# Generated by FakeRAM 2.0
VERSION 5.7 ;
BUSBITCHARS "[]" ;
PROPERTYDEFINITIONS
  MACRO width INTEGER ;
  MACRO depth INTEGER ;
  MACRO banks INTEGER ;
END PROPERTYDEFINITIONS
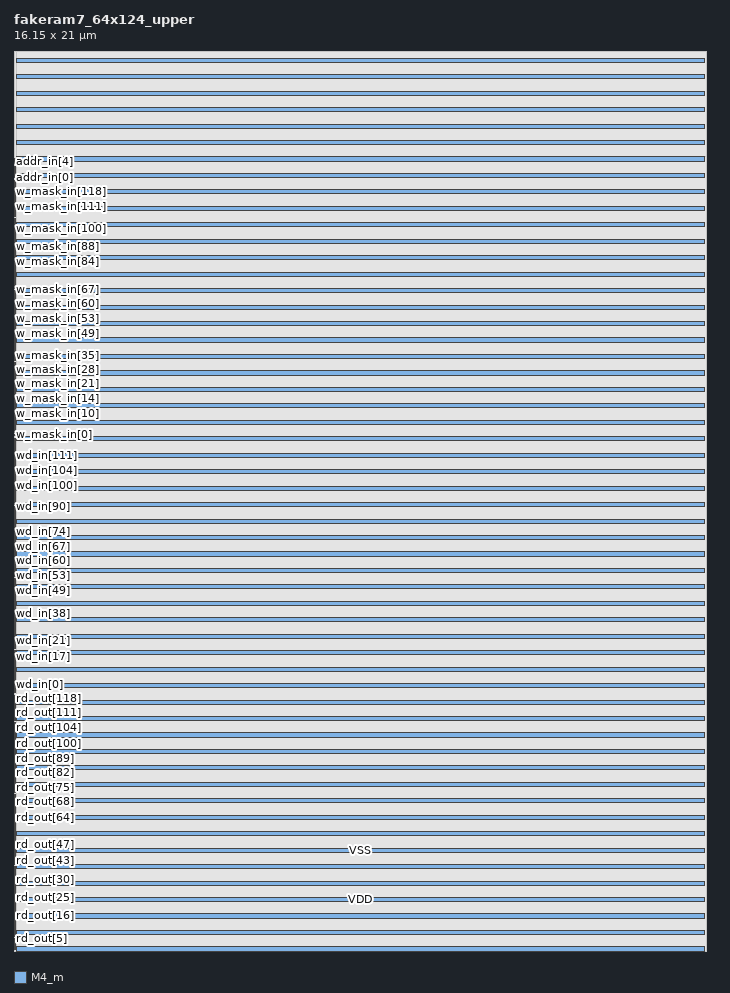
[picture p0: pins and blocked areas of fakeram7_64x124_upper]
MACRO fakeram7_64x124_upper
  PROPERTY width 124 ;
  PROPERTY depth 64 ;
  PROPERTY banks 2 ;
  FOREIGN fakeram7_64x124_upper 0 0 ;
  SYMMETRY X R90 ;
  SIZE 16.150 BY 21.000 ;
  CLASS BLOCK ;
  PIN rd_out[0]
    DIRECTION OUTPUT ;
    USE SIGNAL ;
    SHAPE ABUTMENT ;
    PORT
      LAYER M4_m ;
      RECT 0.000 0.039 0.024 0.063 ;
    END
  END rd_out[0]
  PIN rd_out[1]
    DIRECTION OUTPUT ;
    USE SIGNAL ;
    SHAPE ABUTMENT ;
    PORT
      LAYER M4_m ;
      RECT 0.000 0.087 0.024 0.111 ;
    END
  END rd_out[1]
  PIN rd_out[2]
    DIRECTION OUTPUT ;
    USE SIGNAL ;
    SHAPE ABUTMENT ;
    PORT
      LAYER M4_m ;
      RECT 0.000 0.135 0.024 0.159 ;
    END
  END rd_out[2]
  PIN rd_out[3]
    DIRECTION OUTPUT ;
    USE SIGNAL ;
    SHAPE ABUTMENT ;
    PORT
      LAYER M4_m ;
      RECT 0.000 0.183 0.024 0.207 ;
    END
  END rd_out[3]
  PIN rd_out[4]
    DIRECTION OUTPUT ;
    USE SIGNAL ;
    SHAPE ABUTMENT ;
    PORT
      LAYER M4_m ;
      RECT 0.000 0.231 0.024 0.255 ;
    END
  END rd_out[4]
  PIN rd_out[5]
    DIRECTION OUTPUT ;
    USE SIGNAL ;
    SHAPE ABUTMENT ;
    PORT
      LAYER M4_m ;
      RECT 0.000 0.279 0.024 0.303 ;
    END
  END rd_out[5]
  PIN rd_out[6]
    DIRECTION OUTPUT ;
    USE SIGNAL ;
    SHAPE ABUTMENT ;
    PORT
      LAYER M4_m ;
      RECT 0.000 0.327 0.024 0.351 ;
    END
  END rd_out[6]
  PIN rd_out[7]
    DIRECTION OUTPUT ;
    USE SIGNAL ;
    SHAPE ABUTMENT ;
    PORT
      LAYER M4_m ;
      RECT 0.000 0.375 0.024 0.399 ;
    END
  END rd_out[7]
  PIN rd_out[8]
    DIRECTION OUTPUT ;
    USE SIGNAL ;
    SHAPE ABUTMENT ;
    PORT
      LAYER M4_m ;
      RECT 0.000 0.423 0.024 0.447 ;
    END
  END rd_out[8]
  PIN rd_out[9]
    DIRECTION OUTPUT ;
    USE SIGNAL ;
    SHAPE ABUTMENT ;
    PORT
      LAYER M4_m ;
      RECT 0.000 0.471 0.024 0.495 ;
    END
  END rd_out[9]
  PIN rd_out[10]
    DIRECTION OUTPUT ;
    USE SIGNAL ;
    SHAPE ABUTMENT ;
    PORT
      LAYER M4_m ;
      RECT 0.000 0.519 0.024 0.543 ;
    END
  END rd_out[10]
  PIN rd_out[11]
    DIRECTION OUTPUT ;
    USE SIGNAL ;
    SHAPE ABUTMENT ;
    PORT
      LAYER M4_m ;
      RECT 0.000 0.567 0.024 0.591 ;
    END
  END rd_out[11]
  PIN rd_out[12]
    DIRECTION OUTPUT ;
    USE SIGNAL ;
    SHAPE ABUTMENT ;
    PORT
      LAYER M4_m ;
      RECT 0.000 0.615 0.024 0.639 ;
    END
  END rd_out[12]
  PIN rd_out[13]
    DIRECTION OUTPUT ;
    USE SIGNAL ;
    SHAPE ABUTMENT ;
    PORT
      LAYER M4_m ;
      RECT 0.000 0.663 0.024 0.687 ;
    END
  END rd_out[13]
  PIN rd_out[14]
    DIRECTION OUTPUT ;
    USE SIGNAL ;
    SHAPE ABUTMENT ;
    PORT
      LAYER M4_m ;
      RECT 0.000 0.711 0.024 0.735 ;
    END
  END rd_out[14]
  PIN rd_out[15]
    DIRECTION OUTPUT ;
    USE SIGNAL ;
    SHAPE ABUTMENT ;
    PORT
      LAYER M4_m ;
      RECT 0.000 0.759 0.024 0.783 ;
    END
  END rd_out[15]
  PIN rd_out[16]
    DIRECTION OUTPUT ;
    USE SIGNAL ;
    SHAPE ABUTMENT ;
    PORT
      LAYER M4_m ;
      RECT 0.000 0.807 0.024 0.831 ;
    END
  END rd_out[16]
  PIN rd_out[17]
    DIRECTION OUTPUT ;
    USE SIGNAL ;
    SHAPE ABUTMENT ;
    PORT
      LAYER M4_m ;
      RECT 0.000 0.855 0.024 0.879 ;
    END
  END rd_out[17]
  PIN rd_out[18]
    DIRECTION OUTPUT ;
    USE SIGNAL ;
    SHAPE ABUTMENT ;
    PORT
      LAYER M4_m ;
      RECT 0.000 0.903 0.024 0.927 ;
    END
  END rd_out[18]
  PIN rd_out[19]
    DIRECTION OUTPUT ;
    USE SIGNAL ;
    SHAPE ABUTMENT ;
    PORT
      LAYER M4_m ;
      RECT 0.000 0.951 0.024 0.975 ;
    END
  END rd_out[19]
  PIN rd_out[20]
    DIRECTION OUTPUT ;
    USE SIGNAL ;
    SHAPE ABUTMENT ;
    PORT
      LAYER M4_m ;
      RECT 0.000 0.999 0.024 1.023 ;
    END
  END rd_out[20]
  PIN rd_out[21]
    DIRECTION OUTPUT ;
    USE SIGNAL ;
    SHAPE ABUTMENT ;
    PORT
      LAYER M4_m ;
      RECT 0.000 1.047 0.024 1.071 ;
    END
  END rd_out[21]
  PIN rd_out[22]
    DIRECTION OUTPUT ;
    USE SIGNAL ;
    SHAPE ABUTMENT ;
    PORT
      LAYER M4_m ;
      RECT 0.000 1.095 0.024 1.119 ;
    END
  END rd_out[22]
  PIN rd_out[23]
    DIRECTION OUTPUT ;
    USE SIGNAL ;
    SHAPE ABUTMENT ;
    PORT
      LAYER M4_m ;
      RECT 0.000 1.143 0.024 1.167 ;
    END
  END rd_out[23]
  PIN rd_out[24]
    DIRECTION OUTPUT ;
    USE SIGNAL ;
    SHAPE ABUTMENT ;
    PORT
      LAYER M4_m ;
      RECT 0.000 1.191 0.024 1.215 ;
    END
  END rd_out[24]
  PIN rd_out[25]
    DIRECTION OUTPUT ;
    USE SIGNAL ;
    SHAPE ABUTMENT ;
    PORT
      LAYER M4_m ;
      RECT 0.000 1.239 0.024 1.263 ;
    END
  END rd_out[25]
  PIN rd_out[26]
    DIRECTION OUTPUT ;
    USE SIGNAL ;
    SHAPE ABUTMENT ;
    PORT
      LAYER M4_m ;
      RECT 0.000 1.287 0.024 1.311 ;
    END
  END rd_out[26]
  PIN rd_out[27]
    DIRECTION OUTPUT ;
    USE SIGNAL ;
    SHAPE ABUTMENT ;
    PORT
      LAYER M4_m ;
      RECT 0.000 1.335 0.024 1.359 ;
    END
  END rd_out[27]
  PIN rd_out[28]
    DIRECTION OUTPUT ;
    USE SIGNAL ;
    SHAPE ABUTMENT ;
    PORT
      LAYER M4_m ;
      RECT 0.000 1.383 0.024 1.407 ;
    END
  END rd_out[28]
  PIN rd_out[29]
    DIRECTION OUTPUT ;
    USE SIGNAL ;
    SHAPE ABUTMENT ;
    PORT
      LAYER M4_m ;
      RECT 0.000 1.431 0.024 1.455 ;
    END
  END rd_out[29]
  PIN rd_out[30]
    DIRECTION OUTPUT ;
    USE SIGNAL ;
    SHAPE ABUTMENT ;
    PORT
      LAYER M4_m ;
      RECT 0.000 1.479 0.024 1.503 ;
    END
  END rd_out[30]
  PIN rd_out[31]
    DIRECTION OUTPUT ;
    USE SIGNAL ;
    SHAPE ABUTMENT ;
    PORT
      LAYER M4_m ;
      RECT 0.000 1.527 0.024 1.551 ;
    END
  END rd_out[31]
  PIN rd_out[32]
    DIRECTION OUTPUT ;
    USE SIGNAL ;
    SHAPE ABUTMENT ;
    PORT
      LAYER M4_m ;
      RECT 0.000 1.575 0.024 1.599 ;
    END
  END rd_out[32]
  PIN rd_out[33]
    DIRECTION OUTPUT ;
    USE SIGNAL ;
    SHAPE ABUTMENT ;
    PORT
      LAYER M4_m ;
      RECT 0.000 1.623 0.024 1.647 ;
    END
  END rd_out[33]
  PIN rd_out[34]
    DIRECTION OUTPUT ;
    USE SIGNAL ;
    SHAPE ABUTMENT ;
    PORT
      LAYER M4_m ;
      RECT 0.000 1.671 0.024 1.695 ;
    END
  END rd_out[34]
  PIN rd_out[35]
    DIRECTION OUTPUT ;
    USE SIGNAL ;
    SHAPE ABUTMENT ;
    PORT
      LAYER M4_m ;
      RECT 0.000 1.719 0.024 1.743 ;
    END
  END rd_out[35]
  PIN rd_out[36]
    DIRECTION OUTPUT ;
    USE SIGNAL ;
    SHAPE ABUTMENT ;
    PORT
      LAYER M4_m ;
      RECT 0.000 1.767 0.024 1.791 ;
    END
  END rd_out[36]
  PIN rd_out[37]
    DIRECTION OUTPUT ;
    USE SIGNAL ;
    SHAPE ABUTMENT ;
    PORT
      LAYER M4_m ;
      RECT 0.000 1.815 0.024 1.839 ;
    END
  END rd_out[37]
  PIN rd_out[38]
    DIRECTION OUTPUT ;
    USE SIGNAL ;
    SHAPE ABUTMENT ;
    PORT
      LAYER M4_m ;
      RECT 0.000 1.863 0.024 1.887 ;
    END
  END rd_out[38]
  PIN rd_out[39]
    DIRECTION OUTPUT ;
    USE SIGNAL ;
    SHAPE ABUTMENT ;
    PORT
      LAYER M4_m ;
      RECT 0.000 1.911 0.024 1.935 ;
    END
  END rd_out[39]
  PIN rd_out[40]
    DIRECTION OUTPUT ;
    USE SIGNAL ;
    SHAPE ABUTMENT ;
    PORT
      LAYER M4_m ;
      RECT 0.000 1.959 0.024 1.983 ;
    END
  END rd_out[40]
  PIN rd_out[41]
    DIRECTION OUTPUT ;
    USE SIGNAL ;
    SHAPE ABUTMENT ;
    PORT
      LAYER M4_m ;
      RECT 0.000 2.007 0.024 2.031 ;
    END
  END rd_out[41]
  PIN rd_out[42]
    DIRECTION OUTPUT ;
    USE SIGNAL ;
    SHAPE ABUTMENT ;
    PORT
      LAYER M4_m ;
      RECT 0.000 2.055 0.024 2.079 ;
    END
  END rd_out[42]
  PIN rd_out[43]
    DIRECTION OUTPUT ;
    USE SIGNAL ;
    SHAPE ABUTMENT ;
    PORT
      LAYER M4_m ;
      RECT 0.000 2.103 0.024 2.127 ;
    END
  END rd_out[43]
  PIN rd_out[44]
    DIRECTION OUTPUT ;
    USE SIGNAL ;
    SHAPE ABUTMENT ;
    PORT
      LAYER M4_m ;
      RECT 0.000 2.151 0.024 2.175 ;
    END
  END rd_out[44]
  PIN rd_out[45]
    DIRECTION OUTPUT ;
    USE SIGNAL ;
    SHAPE ABUTMENT ;
    PORT
      LAYER M4_m ;
      RECT 0.000 2.199 0.024 2.223 ;
    END
  END rd_out[45]
  PIN rd_out[46]
    DIRECTION OUTPUT ;
    USE SIGNAL ;
    SHAPE ABUTMENT ;
    PORT
      LAYER M4_m ;
      RECT 0.000 2.247 0.024 2.271 ;
    END
  END rd_out[46]
  PIN rd_out[47]
    DIRECTION OUTPUT ;
    USE SIGNAL ;
    SHAPE ABUTMENT ;
    PORT
      LAYER M4_m ;
      RECT 0.000 2.295 0.024 2.319 ;
    END
  END rd_out[47]
  PIN rd_out[48]
    DIRECTION OUTPUT ;
    USE SIGNAL ;
    SHAPE ABUTMENT ;
    PORT
      LAYER M4_m ;
      RECT 0.000 2.343 0.024 2.367 ;
    END
  END rd_out[48]
  PIN rd_out[49]
    DIRECTION OUTPUT ;
    USE SIGNAL ;
    SHAPE ABUTMENT ;
    PORT
      LAYER M4_m ;
      RECT 0.000 2.391 0.024 2.415 ;
    END
  END rd_out[49]
  PIN rd_out[50]
    DIRECTION OUTPUT ;
    USE SIGNAL ;
    SHAPE ABUTMENT ;
    PORT
      LAYER M4_m ;
      RECT 0.000 2.439 0.024 2.463 ;
    END
  END rd_out[50]
  PIN rd_out[51]
    DIRECTION OUTPUT ;
    USE SIGNAL ;
    SHAPE ABUTMENT ;
    PORT
      LAYER M4_m ;
      RECT 0.000 2.487 0.024 2.511 ;
    END
  END rd_out[51]
  PIN rd_out[52]
    DIRECTION OUTPUT ;
    USE SIGNAL ;
    SHAPE ABUTMENT ;
    PORT
      LAYER M4_m ;
      RECT 0.000 2.535 0.024 2.559 ;
    END
  END rd_out[52]
  PIN rd_out[53]
    DIRECTION OUTPUT ;
    USE SIGNAL ;
    SHAPE ABUTMENT ;
    PORT
      LAYER M4_m ;
      RECT 0.000 2.583 0.024 2.607 ;
    END
  END rd_out[53]
  PIN rd_out[54]
    DIRECTION OUTPUT ;
    USE SIGNAL ;
    SHAPE ABUTMENT ;
    PORT
      LAYER M4_m ;
      RECT 0.000 2.631 0.024 2.655 ;
    END
  END rd_out[54]
  PIN rd_out[55]
    DIRECTION OUTPUT ;
    USE SIGNAL ;
    SHAPE ABUTMENT ;
    PORT
      LAYER M4_m ;
      RECT 0.000 2.679 0.024 2.703 ;
    END
  END rd_out[55]
  PIN rd_out[56]
    DIRECTION OUTPUT ;
    USE SIGNAL ;
    SHAPE ABUTMENT ;
    PORT
      LAYER M4_m ;
      RECT 0.000 2.727 0.024 2.751 ;
    END
  END rd_out[56]
  PIN rd_out[57]
    DIRECTION OUTPUT ;
    USE SIGNAL ;
    SHAPE ABUTMENT ;
    PORT
      LAYER M4_m ;
      RECT 0.000 2.775 0.024 2.799 ;
    END
  END rd_out[57]
  PIN rd_out[58]
    DIRECTION OUTPUT ;
    USE SIGNAL ;
    SHAPE ABUTMENT ;
    PORT
      LAYER M4_m ;
      RECT 0.000 2.823 0.024 2.847 ;
    END
  END rd_out[58]
  PIN rd_out[59]
    DIRECTION OUTPUT ;
    USE SIGNAL ;
    SHAPE ABUTMENT ;
    PORT
      LAYER M4_m ;
      RECT 0.000 2.871 0.024 2.895 ;
    END
  END rd_out[59]
  PIN rd_out[60]
    DIRECTION OUTPUT ;
    USE SIGNAL ;
    SHAPE ABUTMENT ;
    PORT
      LAYER M4_m ;
      RECT 0.000 2.919 0.024 2.943 ;
    END
  END rd_out[60]
  PIN rd_out[61]
    DIRECTION OUTPUT ;
    USE SIGNAL ;
    SHAPE ABUTMENT ;
    PORT
      LAYER M4_m ;
      RECT 0.000 2.967 0.024 2.991 ;
    END
  END rd_out[61]
  PIN rd_out[62]
    DIRECTION OUTPUT ;
    USE SIGNAL ;
    SHAPE ABUTMENT ;
    PORT
      LAYER M4_m ;
      RECT 0.000 3.015 0.024 3.039 ;
    END
  END rd_out[62]
  PIN rd_out[63]
    DIRECTION OUTPUT ;
    USE SIGNAL ;
    SHAPE ABUTMENT ;
    PORT
      LAYER M4_m ;
      RECT 0.000 3.063 0.024 3.087 ;
    END
  END rd_out[63]
  PIN rd_out[64]
    DIRECTION OUTPUT ;
    USE SIGNAL ;
    SHAPE ABUTMENT ;
    PORT
      LAYER M4_m ;
      RECT 0.000 3.111 0.024 3.135 ;
    END
  END rd_out[64]
  PIN rd_out[65]
    DIRECTION OUTPUT ;
    USE SIGNAL ;
    SHAPE ABUTMENT ;
    PORT
      LAYER M4_m ;
      RECT 0.000 3.159 0.024 3.183 ;
    END
  END rd_out[65]
  PIN rd_out[66]
    DIRECTION OUTPUT ;
    USE SIGNAL ;
    SHAPE ABUTMENT ;
    PORT
      LAYER M4_m ;
      RECT 0.000 3.207 0.024 3.231 ;
    END
  END rd_out[66]
  PIN rd_out[67]
    DIRECTION OUTPUT ;
    USE SIGNAL ;
    SHAPE ABUTMENT ;
    PORT
      LAYER M4_m ;
      RECT 0.000 3.255 0.024 3.279 ;
    END
  END rd_out[67]
  PIN rd_out[68]
    DIRECTION OUTPUT ;
    USE SIGNAL ;
    SHAPE ABUTMENT ;
    PORT
      LAYER M4_m ;
      RECT 0.000 3.303 0.024 3.327 ;
    END
  END rd_out[68]
  PIN rd_out[69]
    DIRECTION OUTPUT ;
    USE SIGNAL ;
    SHAPE ABUTMENT ;
    PORT
      LAYER M4_m ;
      RECT 0.000 3.351 0.024 3.375 ;
    END
  END rd_out[69]
  PIN rd_out[70]
    DIRECTION OUTPUT ;
    USE SIGNAL ;
    SHAPE ABUTMENT ;
    PORT
      LAYER M4_m ;
      RECT 0.000 3.399 0.024 3.423 ;
    END
  END rd_out[70]
  PIN rd_out[71]
    DIRECTION OUTPUT ;
    USE SIGNAL ;
    SHAPE ABUTMENT ;
    PORT
      LAYER M4_m ;
      RECT 0.000 3.447 0.024 3.471 ;
    END
  END rd_out[71]
  PIN rd_out[72]
    DIRECTION OUTPUT ;
    USE SIGNAL ;
    SHAPE ABUTMENT ;
    PORT
      LAYER M4_m ;
      RECT 0.000 3.495 0.024 3.519 ;
    END
  END rd_out[72]
  PIN rd_out[73]
    DIRECTION OUTPUT ;
    USE SIGNAL ;
    SHAPE ABUTMENT ;
    PORT
      LAYER M4_m ;
      RECT 0.000 3.543 0.024 3.567 ;
    END
  END rd_out[73]
  PIN rd_out[74]
    DIRECTION OUTPUT ;
    USE SIGNAL ;
    SHAPE ABUTMENT ;
    PORT
      LAYER M4_m ;
      RECT 0.000 3.591 0.024 3.615 ;
    END
  END rd_out[74]
  PIN rd_out[75]
    DIRECTION OUTPUT ;
    USE SIGNAL ;
    SHAPE ABUTMENT ;
    PORT
      LAYER M4_m ;
      RECT 0.000 3.639 0.024 3.663 ;
    END
  END rd_out[75]
  PIN rd_out[76]
    DIRECTION OUTPUT ;
    USE SIGNAL ;
    SHAPE ABUTMENT ;
    PORT
      LAYER M4_m ;
      RECT 0.000 3.687 0.024 3.711 ;
    END
  END rd_out[76]
  PIN rd_out[77]
    DIRECTION OUTPUT ;
    USE SIGNAL ;
    SHAPE ABUTMENT ;
    PORT
      LAYER M4_m ;
      RECT 0.000 3.735 0.024 3.759 ;
    END
  END rd_out[77]
  PIN rd_out[78]
    DIRECTION OUTPUT ;
    USE SIGNAL ;
    SHAPE ABUTMENT ;
    PORT
      LAYER M4_m ;
      RECT 0.000 3.783 0.024 3.807 ;
    END
  END rd_out[78]
  PIN rd_out[79]
    DIRECTION OUTPUT ;
    USE SIGNAL ;
    SHAPE ABUTMENT ;
    PORT
      LAYER M4_m ;
      RECT 0.000 3.831 0.024 3.855 ;
    END
  END rd_out[79]
  PIN rd_out[80]
    DIRECTION OUTPUT ;
    USE SIGNAL ;
    SHAPE ABUTMENT ;
    PORT
      LAYER M4_m ;
      RECT 0.000 3.879 0.024 3.903 ;
    END
  END rd_out[80]
  PIN rd_out[81]
    DIRECTION OUTPUT ;
    USE SIGNAL ;
    SHAPE ABUTMENT ;
    PORT
      LAYER M4_m ;
      RECT 0.000 3.927 0.024 3.951 ;
    END
  END rd_out[81]
  PIN rd_out[82]
    DIRECTION OUTPUT ;
    USE SIGNAL ;
    SHAPE ABUTMENT ;
    PORT
      LAYER M4_m ;
      RECT 0.000 3.975 0.024 3.999 ;
    END
  END rd_out[82]
  PIN rd_out[83]
    DIRECTION OUTPUT ;
    USE SIGNAL ;
    SHAPE ABUTMENT ;
    PORT
      LAYER M4_m ;
      RECT 0.000 4.023 0.024 4.047 ;
    END
  END rd_out[83]
  PIN rd_out[84]
    DIRECTION OUTPUT ;
    USE SIGNAL ;
    SHAPE ABUTMENT ;
    PORT
      LAYER M4_m ;
      RECT 0.000 4.071 0.024 4.095 ;
    END
  END rd_out[84]
  PIN rd_out[85]
    DIRECTION OUTPUT ;
    USE SIGNAL ;
    SHAPE ABUTMENT ;
    PORT
      LAYER M4_m ;
      RECT 0.000 4.119 0.024 4.143 ;
    END
  END rd_out[85]
  PIN rd_out[86]
    DIRECTION OUTPUT ;
    USE SIGNAL ;
    SHAPE ABUTMENT ;
    PORT
      LAYER M4_m ;
      RECT 0.000 4.167 0.024 4.191 ;
    END
  END rd_out[86]
  PIN rd_out[87]
    DIRECTION OUTPUT ;
    USE SIGNAL ;
    SHAPE ABUTMENT ;
    PORT
      LAYER M4_m ;
      RECT 0.000 4.215 0.024 4.239 ;
    END
  END rd_out[87]
  PIN rd_out[88]
    DIRECTION OUTPUT ;
    USE SIGNAL ;
    SHAPE ABUTMENT ;
    PORT
      LAYER M4_m ;
      RECT 0.000 4.263 0.024 4.287 ;
    END
  END rd_out[88]
  PIN rd_out[89]
    DIRECTION OUTPUT ;
    USE SIGNAL ;
    SHAPE ABUTMENT ;
    PORT
      LAYER M4_m ;
      RECT 0.000 4.311 0.024 4.335 ;
    END
  END rd_out[89]
  PIN rd_out[90]
    DIRECTION OUTPUT ;
    USE SIGNAL ;
    SHAPE ABUTMENT ;
    PORT
      LAYER M4_m ;
      RECT 0.000 4.359 0.024 4.383 ;
    END
  END rd_out[90]
  PIN rd_out[91]
    DIRECTION OUTPUT ;
    USE SIGNAL ;
    SHAPE ABUTMENT ;
    PORT
      LAYER M4_m ;
      RECT 0.000 4.407 0.024 4.431 ;
    END
  END rd_out[91]
  PIN rd_out[92]
    DIRECTION OUTPUT ;
    USE SIGNAL ;
    SHAPE ABUTMENT ;
    PORT
      LAYER M4_m ;
      RECT 0.000 4.455 0.024 4.479 ;
    END
  END rd_out[92]
  PIN rd_out[93]
    DIRECTION OUTPUT ;
    USE SIGNAL ;
    SHAPE ABUTMENT ;
    PORT
      LAYER M4_m ;
      RECT 0.000 4.503 0.024 4.527 ;
    END
  END rd_out[93]
  PIN rd_out[94]
    DIRECTION OUTPUT ;
    USE SIGNAL ;
    SHAPE ABUTMENT ;
    PORT
      LAYER M4_m ;
      RECT 0.000 4.551 0.024 4.575 ;
    END
  END rd_out[94]
  PIN rd_out[95]
    DIRECTION OUTPUT ;
    USE SIGNAL ;
    SHAPE ABUTMENT ;
    PORT
      LAYER M4_m ;
      RECT 0.000 4.599 0.024 4.623 ;
    END
  END rd_out[95]
  PIN rd_out[96]
    DIRECTION OUTPUT ;
    USE SIGNAL ;
    SHAPE ABUTMENT ;
    PORT
      LAYER M4_m ;
      RECT 0.000 4.647 0.024 4.671 ;
    END
  END rd_out[96]
  PIN rd_out[97]
    DIRECTION OUTPUT ;
    USE SIGNAL ;
    SHAPE ABUTMENT ;
    PORT
      LAYER M4_m ;
      RECT 0.000 4.695 0.024 4.719 ;
    END
  END rd_out[97]
  PIN rd_out[98]
    DIRECTION OUTPUT ;
    USE SIGNAL ;
    SHAPE ABUTMENT ;
    PORT
      LAYER M4_m ;
      RECT 0.000 4.743 0.024 4.767 ;
    END
  END rd_out[98]
  PIN rd_out[99]
    DIRECTION OUTPUT ;
    USE SIGNAL ;
    SHAPE ABUTMENT ;
    PORT
      LAYER M4_m ;
      RECT 0.000 4.791 0.024 4.815 ;
    END
  END rd_out[99]
  PIN rd_out[100]
    DIRECTION OUTPUT ;
    USE SIGNAL ;
    SHAPE ABUTMENT ;
    PORT
      LAYER M4_m ;
      RECT 0.000 4.839 0.024 4.863 ;
    END
  END rd_out[100]
  PIN rd_out[101]
    DIRECTION OUTPUT ;
    USE SIGNAL ;
    SHAPE ABUTMENT ;
    PORT
      LAYER M4_m ;
      RECT 0.000 4.887 0.024 4.911 ;
    END
  END rd_out[101]
  PIN rd_out[102]
    DIRECTION OUTPUT ;
    USE SIGNAL ;
    SHAPE ABUTMENT ;
    PORT
      LAYER M4_m ;
      RECT 0.000 4.935 0.024 4.959 ;
    END
  END rd_out[102]
  PIN rd_out[103]
    DIRECTION OUTPUT ;
    USE SIGNAL ;
    SHAPE ABUTMENT ;
    PORT
      LAYER M4_m ;
      RECT 0.000 4.983 0.024 5.007 ;
    END
  END rd_out[103]
  PIN rd_out[104]
    DIRECTION OUTPUT ;
    USE SIGNAL ;
    SHAPE ABUTMENT ;
    PORT
      LAYER M4_m ;
      RECT 0.000 5.031 0.024 5.055 ;
    END
  END rd_out[104]
  PIN rd_out[105]
    DIRECTION OUTPUT ;
    USE SIGNAL ;
    SHAPE ABUTMENT ;
    PORT
      LAYER M4_m ;
      RECT 0.000 5.079 0.024 5.103 ;
    END
  END rd_out[105]
  PIN rd_out[106]
    DIRECTION OUTPUT ;
    USE SIGNAL ;
    SHAPE ABUTMENT ;
    PORT
      LAYER M4_m ;
      RECT 0.000 5.127 0.024 5.151 ;
    END
  END rd_out[106]
  PIN rd_out[107]
    DIRECTION OUTPUT ;
    USE SIGNAL ;
    SHAPE ABUTMENT ;
    PORT
      LAYER M4_m ;
      RECT 0.000 5.175 0.024 5.199 ;
    END
  END rd_out[107]
  PIN rd_out[108]
    DIRECTION OUTPUT ;
    USE SIGNAL ;
    SHAPE ABUTMENT ;
    PORT
      LAYER M4_m ;
      RECT 0.000 5.223 0.024 5.247 ;
    END
  END rd_out[108]
  PIN rd_out[109]
    DIRECTION OUTPUT ;
    USE SIGNAL ;
    SHAPE ABUTMENT ;
    PORT
      LAYER M4_m ;
      RECT 0.000 5.271 0.024 5.295 ;
    END
  END rd_out[109]
  PIN rd_out[110]
    DIRECTION OUTPUT ;
    USE SIGNAL ;
    SHAPE ABUTMENT ;
    PORT
      LAYER M4_m ;
      RECT 0.000 5.319 0.024 5.343 ;
    END
  END rd_out[110]
  PIN rd_out[111]
    DIRECTION OUTPUT ;
    USE SIGNAL ;
    SHAPE ABUTMENT ;
    PORT
      LAYER M4_m ;
      RECT 0.000 5.367 0.024 5.391 ;
    END
  END rd_out[111]
  PIN rd_out[112]
    DIRECTION OUTPUT ;
    USE SIGNAL ;
    SHAPE ABUTMENT ;
    PORT
      LAYER M4_m ;
      RECT 0.000 5.415 0.024 5.439 ;
    END
  END rd_out[112]
  PIN rd_out[113]
    DIRECTION OUTPUT ;
    USE SIGNAL ;
    SHAPE ABUTMENT ;
    PORT
      LAYER M4_m ;
      RECT 0.000 5.463 0.024 5.487 ;
    END
  END rd_out[113]
  PIN rd_out[114]
    DIRECTION OUTPUT ;
    USE SIGNAL ;
    SHAPE ABUTMENT ;
    PORT
      LAYER M4_m ;
      RECT 0.000 5.511 0.024 5.535 ;
    END
  END rd_out[114]
  PIN rd_out[115]
    DIRECTION OUTPUT ;
    USE SIGNAL ;
    SHAPE ABUTMENT ;
    PORT
      LAYER M4_m ;
      RECT 0.000 5.559 0.024 5.583 ;
    END
  END rd_out[115]
  PIN rd_out[116]
    DIRECTION OUTPUT ;
    USE SIGNAL ;
    SHAPE ABUTMENT ;
    PORT
      LAYER M4_m ;
      RECT 0.000 5.607 0.024 5.631 ;
    END
  END rd_out[116]
  PIN rd_out[117]
    DIRECTION OUTPUT ;
    USE SIGNAL ;
    SHAPE ABUTMENT ;
    PORT
      LAYER M4_m ;
      RECT 0.000 5.655 0.024 5.679 ;
    END
  END rd_out[117]
  PIN rd_out[118]
    DIRECTION OUTPUT ;
    USE SIGNAL ;
    SHAPE ABUTMENT ;
    PORT
      LAYER M4_m ;
      RECT 0.000 5.703 0.024 5.727 ;
    END
  END rd_out[118]
  PIN rd_out[119]
    DIRECTION OUTPUT ;
    USE SIGNAL ;
    SHAPE ABUTMENT ;
    PORT
      LAYER M4_m ;
      RECT 0.000 5.751 0.024 5.775 ;
    END
  END rd_out[119]
  PIN rd_out[120]
    DIRECTION OUTPUT ;
    USE SIGNAL ;
    SHAPE ABUTMENT ;
    PORT
      LAYER M4_m ;
      RECT 0.000 5.799 0.024 5.823 ;
    END
  END rd_out[120]
  PIN rd_out[121]
    DIRECTION OUTPUT ;
    USE SIGNAL ;
    SHAPE ABUTMENT ;
    PORT
      LAYER M4_m ;
      RECT 0.000 5.847 0.024 5.871 ;
    END
  END rd_out[121]
  PIN rd_out[122]
    DIRECTION OUTPUT ;
    USE SIGNAL ;
    SHAPE ABUTMENT ;
    PORT
      LAYER M4_m ;
      RECT 0.000 5.895 0.024 5.919 ;
    END
  END rd_out[122]
  PIN rd_out[123]
    DIRECTION OUTPUT ;
    USE SIGNAL ;
    SHAPE ABUTMENT ;
    PORT
      LAYER M4_m ;
      RECT 0.000 5.943 0.024 5.967 ;
    END
  END rd_out[123]
  PIN wd_in[0]
    DIRECTION INPUT ;
    USE SIGNAL ;
    SHAPE ABUTMENT ;
    PORT
      LAYER M4_m ;
      RECT 0.000 6.039 0.024 6.063 ;
    END
  END wd_in[0]
  PIN wd_in[1]
    DIRECTION INPUT ;
    USE SIGNAL ;
    SHAPE ABUTMENT ;
    PORT
      LAYER M4_m ;
      RECT 0.000 6.087 0.024 6.111 ;
    END
  END wd_in[1]
  PIN wd_in[2]
    DIRECTION INPUT ;
    USE SIGNAL ;
    SHAPE ABUTMENT ;
    PORT
      LAYER M4_m ;
      RECT 0.000 6.135 0.024 6.159 ;
    END
  END wd_in[2]
  PIN wd_in[3]
    DIRECTION INPUT ;
    USE SIGNAL ;
    SHAPE ABUTMENT ;
    PORT
      LAYER M4_m ;
      RECT 0.000 6.183 0.024 6.207 ;
    END
  END wd_in[3]
  PIN wd_in[4]
    DIRECTION INPUT ;
    USE SIGNAL ;
    SHAPE ABUTMENT ;
    PORT
      LAYER M4_m ;
      RECT 0.000 6.231 0.024 6.255 ;
    END
  END wd_in[4]
  PIN wd_in[5]
    DIRECTION INPUT ;
    USE SIGNAL ;
    SHAPE ABUTMENT ;
    PORT
      LAYER M4_m ;
      RECT 0.000 6.279 0.024 6.303 ;
    END
  END wd_in[5]
  PIN wd_in[6]
    DIRECTION INPUT ;
    USE SIGNAL ;
    SHAPE ABUTMENT ;
    PORT
      LAYER M4_m ;
      RECT 0.000 6.327 0.024 6.351 ;
    END
  END wd_in[6]
  PIN wd_in[7]
    DIRECTION INPUT ;
    USE SIGNAL ;
    SHAPE ABUTMENT ;
    PORT
      LAYER M4_m ;
      RECT 0.000 6.375 0.024 6.399 ;
    END
  END wd_in[7]
  PIN wd_in[8]
    DIRECTION INPUT ;
    USE SIGNAL ;
    SHAPE ABUTMENT ;
    PORT
      LAYER M4_m ;
      RECT 0.000 6.423 0.024 6.447 ;
    END
  END wd_in[8]
  PIN wd_in[9]
    DIRECTION INPUT ;
    USE SIGNAL ;
    SHAPE ABUTMENT ;
    PORT
      LAYER M4_m ;
      RECT 0.000 6.471 0.024 6.495 ;
    END
  END wd_in[9]
  PIN wd_in[10]
    DIRECTION INPUT ;
    USE SIGNAL ;
    SHAPE ABUTMENT ;
    PORT
      LAYER M4_m ;
      RECT 0.000 6.519 0.024 6.543 ;
    END
  END wd_in[10]
  PIN wd_in[11]
    DIRECTION INPUT ;
    USE SIGNAL ;
    SHAPE ABUTMENT ;
    PORT
      LAYER M4_m ;
      RECT 0.000 6.567 0.024 6.591 ;
    END
  END wd_in[11]
  PIN wd_in[12]
    DIRECTION INPUT ;
    USE SIGNAL ;
    SHAPE ABUTMENT ;
    PORT
      LAYER M4_m ;
      RECT 0.000 6.615 0.024 6.639 ;
    END
  END wd_in[12]
  PIN wd_in[13]
    DIRECTION INPUT ;
    USE SIGNAL ;
    SHAPE ABUTMENT ;
    PORT
      LAYER M4_m ;
      RECT 0.000 6.663 0.024 6.687 ;
    END
  END wd_in[13]
  PIN wd_in[14]
    DIRECTION INPUT ;
    USE SIGNAL ;
    SHAPE ABUTMENT ;
    PORT
      LAYER M4_m ;
      RECT 0.000 6.711 0.024 6.735 ;
    END
  END wd_in[14]
  PIN wd_in[15]
    DIRECTION INPUT ;
    USE SIGNAL ;
    SHAPE ABUTMENT ;
    PORT
      LAYER M4_m ;
      RECT 0.000 6.759 0.024 6.783 ;
    END
  END wd_in[15]
  PIN wd_in[16]
    DIRECTION INPUT ;
    USE SIGNAL ;
    SHAPE ABUTMENT ;
    PORT
      LAYER M4_m ;
      RECT 0.000 6.807 0.024 6.831 ;
    END
  END wd_in[16]
  PIN wd_in[17]
    DIRECTION INPUT ;
    USE SIGNAL ;
    SHAPE ABUTMENT ;
    PORT
      LAYER M4_m ;
      RECT 0.000 6.855 0.024 6.879 ;
    END
  END wd_in[17]
  PIN wd_in[18]
    DIRECTION INPUT ;
    USE SIGNAL ;
    SHAPE ABUTMENT ;
    PORT
      LAYER M4_m ;
      RECT 0.000 6.903 0.024 6.927 ;
    END
  END wd_in[18]
  PIN wd_in[19]
    DIRECTION INPUT ;
    USE SIGNAL ;
    SHAPE ABUTMENT ;
    PORT
      LAYER M4_m ;
      RECT 0.000 6.951 0.024 6.975 ;
    END
  END wd_in[19]
  PIN wd_in[20]
    DIRECTION INPUT ;
    USE SIGNAL ;
    SHAPE ABUTMENT ;
    PORT
      LAYER M4_m ;
      RECT 0.000 6.999 0.024 7.023 ;
    END
  END wd_in[20]
  PIN wd_in[21]
    DIRECTION INPUT ;
    USE SIGNAL ;
    SHAPE ABUTMENT ;
    PORT
      LAYER M4_m ;
      RECT 0.000 7.047 0.024 7.071 ;
    END
  END wd_in[21]
  PIN wd_in[22]
    DIRECTION INPUT ;
    USE SIGNAL ;
    SHAPE ABUTMENT ;
    PORT
      LAYER M4_m ;
      RECT 0.000 7.095 0.024 7.119 ;
    END
  END wd_in[22]
  PIN wd_in[23]
    DIRECTION INPUT ;
    USE SIGNAL ;
    SHAPE ABUTMENT ;
    PORT
      LAYER M4_m ;
      RECT 0.000 7.143 0.024 7.167 ;
    END
  END wd_in[23]
  PIN wd_in[24]
    DIRECTION INPUT ;
    USE SIGNAL ;
    SHAPE ABUTMENT ;
    PORT
      LAYER M4_m ;
      RECT 0.000 7.191 0.024 7.215 ;
    END
  END wd_in[24]
  PIN wd_in[25]
    DIRECTION INPUT ;
    USE SIGNAL ;
    SHAPE ABUTMENT ;
    PORT
      LAYER M4_m ;
      RECT 0.000 7.239 0.024 7.263 ;
    END
  END wd_in[25]
  PIN wd_in[26]
    DIRECTION INPUT ;
    USE SIGNAL ;
    SHAPE ABUTMENT ;
    PORT
      LAYER M4_m ;
      RECT 0.000 7.287 0.024 7.311 ;
    END
  END wd_in[26]
  PIN wd_in[27]
    DIRECTION INPUT ;
    USE SIGNAL ;
    SHAPE ABUTMENT ;
    PORT
      LAYER M4_m ;
      RECT 0.000 7.335 0.024 7.359 ;
    END
  END wd_in[27]
  PIN wd_in[28]
    DIRECTION INPUT ;
    USE SIGNAL ;
    SHAPE ABUTMENT ;
    PORT
      LAYER M4_m ;
      RECT 0.000 7.383 0.024 7.407 ;
    END
  END wd_in[28]
  PIN wd_in[29]
    DIRECTION INPUT ;
    USE SIGNAL ;
    SHAPE ABUTMENT ;
    PORT
      LAYER M4_m ;
      RECT 0.000 7.431 0.024 7.455 ;
    END
  END wd_in[29]
  PIN wd_in[30]
    DIRECTION INPUT ;
    USE SIGNAL ;
    SHAPE ABUTMENT ;
    PORT
      LAYER M4_m ;
      RECT 0.000 7.479 0.024 7.503 ;
    END
  END wd_in[30]
  PIN wd_in[31]
    DIRECTION INPUT ;
    USE SIGNAL ;
    SHAPE ABUTMENT ;
    PORT
      LAYER M4_m ;
      RECT 0.000 7.527 0.024 7.551 ;
    END
  END wd_in[31]
  PIN wd_in[32]
    DIRECTION INPUT ;
    USE SIGNAL ;
    SHAPE ABUTMENT ;
    PORT
      LAYER M4_m ;
      RECT 0.000 7.575 0.024 7.599 ;
    END
  END wd_in[32]
  PIN wd_in[33]
    DIRECTION INPUT ;
    USE SIGNAL ;
    SHAPE ABUTMENT ;
    PORT
      LAYER M4_m ;
      RECT 0.000 7.623 0.024 7.647 ;
    END
  END wd_in[33]
  PIN wd_in[34]
    DIRECTION INPUT ;
    USE SIGNAL ;
    SHAPE ABUTMENT ;
    PORT
      LAYER M4_m ;
      RECT 0.000 7.671 0.024 7.695 ;
    END
  END wd_in[34]
  PIN wd_in[35]
    DIRECTION INPUT ;
    USE SIGNAL ;
    SHAPE ABUTMENT ;
    PORT
      LAYER M4_m ;
      RECT 0.000 7.719 0.024 7.743 ;
    END
  END wd_in[35]
  PIN wd_in[36]
    DIRECTION INPUT ;
    USE SIGNAL ;
    SHAPE ABUTMENT ;
    PORT
      LAYER M4_m ;
      RECT 0.000 7.767 0.024 7.791 ;
    END
  END wd_in[36]
  PIN wd_in[37]
    DIRECTION INPUT ;
    USE SIGNAL ;
    SHAPE ABUTMENT ;
    PORT
      LAYER M4_m ;
      RECT 0.000 7.815 0.024 7.839 ;
    END
  END wd_in[37]
  PIN wd_in[38]
    DIRECTION INPUT ;
    USE SIGNAL ;
    SHAPE ABUTMENT ;
    PORT
      LAYER M4_m ;
      RECT 0.000 7.863 0.024 7.887 ;
    END
  END wd_in[38]
  PIN wd_in[39]
    DIRECTION INPUT ;
    USE SIGNAL ;
    SHAPE ABUTMENT ;
    PORT
      LAYER M4_m ;
      RECT 0.000 7.911 0.024 7.935 ;
    END
  END wd_in[39]
  PIN wd_in[40]
    DIRECTION INPUT ;
    USE SIGNAL ;
    SHAPE ABUTMENT ;
    PORT
      LAYER M4_m ;
      RECT 0.000 7.959 0.024 7.983 ;
    END
  END wd_in[40]
  PIN wd_in[41]
    DIRECTION INPUT ;
    USE SIGNAL ;
    SHAPE ABUTMENT ;
    PORT
      LAYER M4_m ;
      RECT 0.000 8.007 0.024 8.031 ;
    END
  END wd_in[41]
  PIN wd_in[42]
    DIRECTION INPUT ;
    USE SIGNAL ;
    SHAPE ABUTMENT ;
    PORT
      LAYER M4_m ;
      RECT 0.000 8.055 0.024 8.079 ;
    END
  END wd_in[42]
  PIN wd_in[43]
    DIRECTION INPUT ;
    USE SIGNAL ;
    SHAPE ABUTMENT ;
    PORT
      LAYER M4_m ;
      RECT 0.000 8.103 0.024 8.127 ;
    END
  END wd_in[43]
  PIN wd_in[44]
    DIRECTION INPUT ;
    USE SIGNAL ;
    SHAPE ABUTMENT ;
    PORT
      LAYER M4_m ;
      RECT 0.000 8.151 0.024 8.175 ;
    END
  END wd_in[44]
  PIN wd_in[45]
    DIRECTION INPUT ;
    USE SIGNAL ;
    SHAPE ABUTMENT ;
    PORT
      LAYER M4_m ;
      RECT 0.000 8.199 0.024 8.223 ;
    END
  END wd_in[45]
  PIN wd_in[46]
    DIRECTION INPUT ;
    USE SIGNAL ;
    SHAPE ABUTMENT ;
    PORT
      LAYER M4_m ;
      RECT 0.000 8.247 0.024 8.271 ;
    END
  END wd_in[46]
  PIN wd_in[47]
    DIRECTION INPUT ;
    USE SIGNAL ;
    SHAPE ABUTMENT ;
    PORT
      LAYER M4_m ;
      RECT 0.000 8.295 0.024 8.319 ;
    END
  END wd_in[47]
  PIN wd_in[48]
    DIRECTION INPUT ;
    USE SIGNAL ;
    SHAPE ABUTMENT ;
    PORT
      LAYER M4_m ;
      RECT 0.000 8.343 0.024 8.367 ;
    END
  END wd_in[48]
  PIN wd_in[49]
    DIRECTION INPUT ;
    USE SIGNAL ;
    SHAPE ABUTMENT ;
    PORT
      LAYER M4_m ;
      RECT 0.000 8.391 0.024 8.415 ;
    END
  END wd_in[49]
  PIN wd_in[50]
    DIRECTION INPUT ;
    USE SIGNAL ;
    SHAPE ABUTMENT ;
    PORT
      LAYER M4_m ;
      RECT 0.000 8.439 0.024 8.463 ;
    END
  END wd_in[50]
  PIN wd_in[51]
    DIRECTION INPUT ;
    USE SIGNAL ;
    SHAPE ABUTMENT ;
    PORT
      LAYER M4_m ;
      RECT 0.000 8.487 0.024 8.511 ;
    END
  END wd_in[51]
  PIN wd_in[52]
    DIRECTION INPUT ;
    USE SIGNAL ;
    SHAPE ABUTMENT ;
    PORT
      LAYER M4_m ;
      RECT 0.000 8.535 0.024 8.559 ;
    END
  END wd_in[52]
  PIN wd_in[53]
    DIRECTION INPUT ;
    USE SIGNAL ;
    SHAPE ABUTMENT ;
    PORT
      LAYER M4_m ;
      RECT 0.000 8.583 0.024 8.607 ;
    END
  END wd_in[53]
  PIN wd_in[54]
    DIRECTION INPUT ;
    USE SIGNAL ;
    SHAPE ABUTMENT ;
    PORT
      LAYER M4_m ;
      RECT 0.000 8.631 0.024 8.655 ;
    END
  END wd_in[54]
  PIN wd_in[55]
    DIRECTION INPUT ;
    USE SIGNAL ;
    SHAPE ABUTMENT ;
    PORT
      LAYER M4_m ;
      RECT 0.000 8.679 0.024 8.703 ;
    END
  END wd_in[55]
  PIN wd_in[56]
    DIRECTION INPUT ;
    USE SIGNAL ;
    SHAPE ABUTMENT ;
    PORT
      LAYER M4_m ;
      RECT 0.000 8.727 0.024 8.751 ;
    END
  END wd_in[56]
  PIN wd_in[57]
    DIRECTION INPUT ;
    USE SIGNAL ;
    SHAPE ABUTMENT ;
    PORT
      LAYER M4_m ;
      RECT 0.000 8.775 0.024 8.799 ;
    END
  END wd_in[57]
  PIN wd_in[58]
    DIRECTION INPUT ;
    USE SIGNAL ;
    SHAPE ABUTMENT ;
    PORT
      LAYER M4_m ;
      RECT 0.000 8.823 0.024 8.847 ;
    END
  END wd_in[58]
  PIN wd_in[59]
    DIRECTION INPUT ;
    USE SIGNAL ;
    SHAPE ABUTMENT ;
    PORT
      LAYER M4_m ;
      RECT 0.000 8.871 0.024 8.895 ;
    END
  END wd_in[59]
  PIN wd_in[60]
    DIRECTION INPUT ;
    USE SIGNAL ;
    SHAPE ABUTMENT ;
    PORT
      LAYER M4_m ;
      RECT 0.000 8.919 0.024 8.943 ;
    END
  END wd_in[60]
  PIN wd_in[61]
    DIRECTION INPUT ;
    USE SIGNAL ;
    SHAPE ABUTMENT ;
    PORT
      LAYER M4_m ;
      RECT 0.000 8.967 0.024 8.991 ;
    END
  END wd_in[61]
  PIN wd_in[62]
    DIRECTION INPUT ;
    USE SIGNAL ;
    SHAPE ABUTMENT ;
    PORT
      LAYER M4_m ;
      RECT 0.000 9.015 0.024 9.039 ;
    END
  END wd_in[62]
  PIN wd_in[63]
    DIRECTION INPUT ;
    USE SIGNAL ;
    SHAPE ABUTMENT ;
    PORT
      LAYER M4_m ;
      RECT 0.000 9.063 0.024 9.087 ;
    END
  END wd_in[63]
  PIN wd_in[64]
    DIRECTION INPUT ;
    USE SIGNAL ;
    SHAPE ABUTMENT ;
    PORT
      LAYER M4_m ;
      RECT 0.000 9.111 0.024 9.135 ;
    END
  END wd_in[64]
  PIN wd_in[65]
    DIRECTION INPUT ;
    USE SIGNAL ;
    SHAPE ABUTMENT ;
    PORT
      LAYER M4_m ;
      RECT 0.000 9.159 0.024 9.183 ;
    END
  END wd_in[65]
  PIN wd_in[66]
    DIRECTION INPUT ;
    USE SIGNAL ;
    SHAPE ABUTMENT ;
    PORT
      LAYER M4_m ;
      RECT 0.000 9.207 0.024 9.231 ;
    END
  END wd_in[66]
  PIN wd_in[67]
    DIRECTION INPUT ;
    USE SIGNAL ;
    SHAPE ABUTMENT ;
    PORT
      LAYER M4_m ;
      RECT 0.000 9.255 0.024 9.279 ;
    END
  END wd_in[67]
  PIN wd_in[68]
    DIRECTION INPUT ;
    USE SIGNAL ;
    SHAPE ABUTMENT ;
    PORT
      LAYER M4_m ;
      RECT 0.000 9.303 0.024 9.327 ;
    END
  END wd_in[68]
  PIN wd_in[69]
    DIRECTION INPUT ;
    USE SIGNAL ;
    SHAPE ABUTMENT ;
    PORT
      LAYER M4_m ;
      RECT 0.000 9.351 0.024 9.375 ;
    END
  END wd_in[69]
  PIN wd_in[70]
    DIRECTION INPUT ;
    USE SIGNAL ;
    SHAPE ABUTMENT ;
    PORT
      LAYER M4_m ;
      RECT 0.000 9.399 0.024 9.423 ;
    END
  END wd_in[70]
  PIN wd_in[71]
    DIRECTION INPUT ;
    USE SIGNAL ;
    SHAPE ABUTMENT ;
    PORT
      LAYER M4_m ;
      RECT 0.000 9.447 0.024 9.471 ;
    END
  END wd_in[71]
  PIN wd_in[72]
    DIRECTION INPUT ;
    USE SIGNAL ;
    SHAPE ABUTMENT ;
    PORT
      LAYER M4_m ;
      RECT 0.000 9.495 0.024 9.519 ;
    END
  END wd_in[72]
  PIN wd_in[73]
    DIRECTION INPUT ;
    USE SIGNAL ;
    SHAPE ABUTMENT ;
    PORT
      LAYER M4_m ;
      RECT 0.000 9.543 0.024 9.567 ;
    END
  END wd_in[73]
  PIN wd_in[74]
    DIRECTION INPUT ;
    USE SIGNAL ;
    SHAPE ABUTMENT ;
    PORT
      LAYER M4_m ;
      RECT 0.000 9.591 0.024 9.615 ;
    END
  END wd_in[74]
  PIN wd_in[75]
    DIRECTION INPUT ;
    USE SIGNAL ;
    SHAPE ABUTMENT ;
    PORT
      LAYER M4_m ;
      RECT 0.000 9.639 0.024 9.663 ;
    END
  END wd_in[75]
  PIN wd_in[76]
    DIRECTION INPUT ;
    USE SIGNAL ;
    SHAPE ABUTMENT ;
    PORT
      LAYER M4_m ;
      RECT 0.000 9.687 0.024 9.711 ;
    END
  END wd_in[76]
  PIN wd_in[77]
    DIRECTION INPUT ;
    USE SIGNAL ;
    SHAPE ABUTMENT ;
    PORT
      LAYER M4_m ;
      RECT 0.000 9.735 0.024 9.759 ;
    END
  END wd_in[77]
  PIN wd_in[78]
    DIRECTION INPUT ;
    USE SIGNAL ;
    SHAPE ABUTMENT ;
    PORT
      LAYER M4_m ;
      RECT 0.000 9.783 0.024 9.807 ;
    END
  END wd_in[78]
  PIN wd_in[79]
    DIRECTION INPUT ;
    USE SIGNAL ;
    SHAPE ABUTMENT ;
    PORT
      LAYER M4_m ;
      RECT 0.000 9.831 0.024 9.855 ;
    END
  END wd_in[79]
  PIN wd_in[80]
    DIRECTION INPUT ;
    USE SIGNAL ;
    SHAPE ABUTMENT ;
    PORT
      LAYER M4_m ;
      RECT 0.000 9.879 0.024 9.903 ;
    END
  END wd_in[80]
  PIN wd_in[81]
    DIRECTION INPUT ;
    USE SIGNAL ;
    SHAPE ABUTMENT ;
    PORT
      LAYER M4_m ;
      RECT 0.000 9.927 0.024 9.951 ;
    END
  END wd_in[81]
  PIN wd_in[82]
    DIRECTION INPUT ;
    USE SIGNAL ;
    SHAPE ABUTMENT ;
    PORT
      LAYER M4_m ;
      RECT 0.000 9.975 0.024 9.999 ;
    END
  END wd_in[82]
  PIN wd_in[83]
    DIRECTION INPUT ;
    USE SIGNAL ;
    SHAPE ABUTMENT ;
    PORT
      LAYER M4_m ;
      RECT 0.000 10.023 0.024 10.047 ;
    END
  END wd_in[83]
  PIN wd_in[84]
    DIRECTION INPUT ;
    USE SIGNAL ;
    SHAPE ABUTMENT ;
    PORT
      LAYER M4_m ;
      RECT 0.000 10.071 0.024 10.095 ;
    END
  END wd_in[84]
  PIN wd_in[85]
    DIRECTION INPUT ;
    USE SIGNAL ;
    SHAPE ABUTMENT ;
    PORT
      LAYER M4_m ;
      RECT 0.000 10.119 0.024 10.143 ;
    END
  END wd_in[85]
  PIN wd_in[86]
    DIRECTION INPUT ;
    USE SIGNAL ;
    SHAPE ABUTMENT ;
    PORT
      LAYER M4_m ;
      RECT 0.000 10.167 0.024 10.191 ;
    END
  END wd_in[86]
  PIN wd_in[87]
    DIRECTION INPUT ;
    USE SIGNAL ;
    SHAPE ABUTMENT ;
    PORT
      LAYER M4_m ;
      RECT 0.000 10.215 0.024 10.239 ;
    END
  END wd_in[87]
  PIN wd_in[88]
    DIRECTION INPUT ;
    USE SIGNAL ;
    SHAPE ABUTMENT ;
    PORT
      LAYER M4_m ;
      RECT 0.000 10.263 0.024 10.287 ;
    END
  END wd_in[88]
  PIN wd_in[89]
    DIRECTION INPUT ;
    USE SIGNAL ;
    SHAPE ABUTMENT ;
    PORT
      LAYER M4_m ;
      RECT 0.000 10.311 0.024 10.335 ;
    END
  END wd_in[89]
  PIN wd_in[90]
    DIRECTION INPUT ;
    USE SIGNAL ;
    SHAPE ABUTMENT ;
    PORT
      LAYER M4_m ;
      RECT 0.000 10.359 0.024 10.383 ;
    END
  END wd_in[90]
  PIN wd_in[91]
    DIRECTION INPUT ;
    USE SIGNAL ;
    SHAPE ABUTMENT ;
    PORT
      LAYER M4_m ;
      RECT 0.000 10.407 0.024 10.431 ;
    END
  END wd_in[91]
  PIN wd_in[92]
    DIRECTION INPUT ;
    USE SIGNAL ;
    SHAPE ABUTMENT ;
    PORT
      LAYER M4_m ;
      RECT 0.000 10.455 0.024 10.479 ;
    END
  END wd_in[92]
  PIN wd_in[93]
    DIRECTION INPUT ;
    USE SIGNAL ;
    SHAPE ABUTMENT ;
    PORT
      LAYER M4_m ;
      RECT 0.000 10.503 0.024 10.527 ;
    END
  END wd_in[93]
  PIN wd_in[94]
    DIRECTION INPUT ;
    USE SIGNAL ;
    SHAPE ABUTMENT ;
    PORT
      LAYER M4_m ;
      RECT 0.000 10.551 0.024 10.575 ;
    END
  END wd_in[94]
  PIN wd_in[95]
    DIRECTION INPUT ;
    USE SIGNAL ;
    SHAPE ABUTMENT ;
    PORT
      LAYER M4_m ;
      RECT 0.000 10.599 0.024 10.623 ;
    END
  END wd_in[95]
  PIN wd_in[96]
    DIRECTION INPUT ;
    USE SIGNAL ;
    SHAPE ABUTMENT ;
    PORT
      LAYER M4_m ;
      RECT 0.000 10.647 0.024 10.671 ;
    END
  END wd_in[96]
  PIN wd_in[97]
    DIRECTION INPUT ;
    USE SIGNAL ;
    SHAPE ABUTMENT ;
    PORT
      LAYER M4_m ;
      RECT 0.000 10.695 0.024 10.719 ;
    END
  END wd_in[97]
  PIN wd_in[98]
    DIRECTION INPUT ;
    USE SIGNAL ;
    SHAPE ABUTMENT ;
    PORT
      LAYER M4_m ;
      RECT 0.000 10.743 0.024 10.767 ;
    END
  END wd_in[98]
  PIN wd_in[99]
    DIRECTION INPUT ;
    USE SIGNAL ;
    SHAPE ABUTMENT ;
    PORT
      LAYER M4_m ;
      RECT 0.000 10.791 0.024 10.815 ;
    END
  END wd_in[99]
  PIN wd_in[100]
    DIRECTION INPUT ;
    USE SIGNAL ;
    SHAPE ABUTMENT ;
    PORT
      LAYER M4_m ;
      RECT 0.000 10.839 0.024 10.863 ;
    END
  END wd_in[100]
  PIN wd_in[101]
    DIRECTION INPUT ;
    USE SIGNAL ;
    SHAPE ABUTMENT ;
    PORT
      LAYER M4_m ;
      RECT 0.000 10.887 0.024 10.911 ;
    END
  END wd_in[101]
  PIN wd_in[102]
    DIRECTION INPUT ;
    USE SIGNAL ;
    SHAPE ABUTMENT ;
    PORT
      LAYER M4_m ;
      RECT 0.000 10.935 0.024 10.959 ;
    END
  END wd_in[102]
  PIN wd_in[103]
    DIRECTION INPUT ;
    USE SIGNAL ;
    SHAPE ABUTMENT ;
    PORT
      LAYER M4_m ;
      RECT 0.000 10.983 0.024 11.007 ;
    END
  END wd_in[103]
  PIN wd_in[104]
    DIRECTION INPUT ;
    USE SIGNAL ;
    SHAPE ABUTMENT ;
    PORT
      LAYER M4_m ;
      RECT 0.000 11.031 0.024 11.055 ;
    END
  END wd_in[104]
  PIN wd_in[105]
    DIRECTION INPUT ;
    USE SIGNAL ;
    SHAPE ABUTMENT ;
    PORT
      LAYER M4_m ;
      RECT 0.000 11.079 0.024 11.103 ;
    END
  END wd_in[105]
  PIN wd_in[106]
    DIRECTION INPUT ;
    USE SIGNAL ;
    SHAPE ABUTMENT ;
    PORT
      LAYER M4_m ;
      RECT 0.000 11.127 0.024 11.151 ;
    END
  END wd_in[106]
  PIN wd_in[107]
    DIRECTION INPUT ;
    USE SIGNAL ;
    SHAPE ABUTMENT ;
    PORT
      LAYER M4_m ;
      RECT 0.000 11.175 0.024 11.199 ;
    END
  END wd_in[107]
  PIN wd_in[108]
    DIRECTION INPUT ;
    USE SIGNAL ;
    SHAPE ABUTMENT ;
    PORT
      LAYER M4_m ;
      RECT 0.000 11.223 0.024 11.247 ;
    END
  END wd_in[108]
  PIN wd_in[109]
    DIRECTION INPUT ;
    USE SIGNAL ;
    SHAPE ABUTMENT ;
    PORT
      LAYER M4_m ;
      RECT 0.000 11.271 0.024 11.295 ;
    END
  END wd_in[109]
  PIN wd_in[110]
    DIRECTION INPUT ;
    USE SIGNAL ;
    SHAPE ABUTMENT ;
    PORT
      LAYER M4_m ;
      RECT 0.000 11.319 0.024 11.343 ;
    END
  END wd_in[110]
  PIN wd_in[111]
    DIRECTION INPUT ;
    USE SIGNAL ;
    SHAPE ABUTMENT ;
    PORT
      LAYER M4_m ;
      RECT 0.000 11.367 0.024 11.391 ;
    END
  END wd_in[111]
  PIN wd_in[112]
    DIRECTION INPUT ;
    USE SIGNAL ;
    SHAPE ABUTMENT ;
    PORT
      LAYER M4_m ;
      RECT 0.000 11.415 0.024 11.439 ;
    END
  END wd_in[112]
  PIN wd_in[113]
    DIRECTION INPUT ;
    USE SIGNAL ;
    SHAPE ABUTMENT ;
    PORT
      LAYER M4_m ;
      RECT 0.000 11.463 0.024 11.487 ;
    END
  END wd_in[113]
  PIN wd_in[114]
    DIRECTION INPUT ;
    USE SIGNAL ;
    SHAPE ABUTMENT ;
    PORT
      LAYER M4_m ;
      RECT 0.000 11.511 0.024 11.535 ;
    END
  END wd_in[114]
  PIN wd_in[115]
    DIRECTION INPUT ;
    USE SIGNAL ;
    SHAPE ABUTMENT ;
    PORT
      LAYER M4_m ;
      RECT 0.000 11.559 0.024 11.583 ;
    END
  END wd_in[115]
  PIN wd_in[116]
    DIRECTION INPUT ;
    USE SIGNAL ;
    SHAPE ABUTMENT ;
    PORT
      LAYER M4_m ;
      RECT 0.000 11.607 0.024 11.631 ;
    END
  END wd_in[116]
  PIN wd_in[117]
    DIRECTION INPUT ;
    USE SIGNAL ;
    SHAPE ABUTMENT ;
    PORT
      LAYER M4_m ;
      RECT 0.000 11.655 0.024 11.679 ;
    END
  END wd_in[117]
  PIN wd_in[118]
    DIRECTION INPUT ;
    USE SIGNAL ;
    SHAPE ABUTMENT ;
    PORT
      LAYER M4_m ;
      RECT 0.000 11.703 0.024 11.727 ;
    END
  END wd_in[118]
  PIN wd_in[119]
    DIRECTION INPUT ;
    USE SIGNAL ;
    SHAPE ABUTMENT ;
    PORT
      LAYER M4_m ;
      RECT 0.000 11.751 0.024 11.775 ;
    END
  END wd_in[119]
  PIN wd_in[120]
    DIRECTION INPUT ;
    USE SIGNAL ;
    SHAPE ABUTMENT ;
    PORT
      LAYER M4_m ;
      RECT 0.000 11.799 0.024 11.823 ;
    END
  END wd_in[120]
  PIN wd_in[121]
    DIRECTION INPUT ;
    USE SIGNAL ;
    SHAPE ABUTMENT ;
    PORT
      LAYER M4_m ;
      RECT 0.000 11.847 0.024 11.871 ;
    END
  END wd_in[121]
  PIN wd_in[122]
    DIRECTION INPUT ;
    USE SIGNAL ;
    SHAPE ABUTMENT ;
    PORT
      LAYER M4_m ;
      RECT 0.000 11.895 0.024 11.919 ;
    END
  END wd_in[122]
  PIN wd_in[123]
    DIRECTION INPUT ;
    USE SIGNAL ;
    SHAPE ABUTMENT ;
    PORT
      LAYER M4_m ;
      RECT 0.000 11.943 0.024 11.967 ;
    END
  END wd_in[123]
  PIN w_mask_in[0]
    DIRECTION INPUT ;
    USE SIGNAL ;
    SHAPE ABUTMENT ;
    PORT
      LAYER M4_m ;
      RECT 0.000 12.039 0.024 12.063 ;
    END
  END w_mask_in[0]
  PIN w_mask_in[1]
    DIRECTION INPUT ;
    USE SIGNAL ;
    SHAPE ABUTMENT ;
    PORT
      LAYER M4_m ;
      RECT 0.000 12.087 0.024 12.111 ;
    END
  END w_mask_in[1]
  PIN w_mask_in[2]
    DIRECTION INPUT ;
    USE SIGNAL ;
    SHAPE ABUTMENT ;
    PORT
      LAYER M4_m ;
      RECT 0.000 12.135 0.024 12.159 ;
    END
  END w_mask_in[2]
  PIN w_mask_in[3]
    DIRECTION INPUT ;
    USE SIGNAL ;
    SHAPE ABUTMENT ;
    PORT
      LAYER M4_m ;
      RECT 0.000 12.183 0.024 12.207 ;
    END
  END w_mask_in[3]
  PIN w_mask_in[4]
    DIRECTION INPUT ;
    USE SIGNAL ;
    SHAPE ABUTMENT ;
    PORT
      LAYER M4_m ;
      RECT 0.000 12.231 0.024 12.255 ;
    END
  END w_mask_in[4]
  PIN w_mask_in[5]
    DIRECTION INPUT ;
    USE SIGNAL ;
    SHAPE ABUTMENT ;
    PORT
      LAYER M4_m ;
      RECT 0.000 12.279 0.024 12.303 ;
    END
  END w_mask_in[5]
  PIN w_mask_in[6]
    DIRECTION INPUT ;
    USE SIGNAL ;
    SHAPE ABUTMENT ;
    PORT
      LAYER M4_m ;
      RECT 0.000 12.327 0.024 12.351 ;
    END
  END w_mask_in[6]
  PIN w_mask_in[7]
    DIRECTION INPUT ;
    USE SIGNAL ;
    SHAPE ABUTMENT ;
    PORT
      LAYER M4_m ;
      RECT 0.000 12.375 0.024 12.399 ;
    END
  END w_mask_in[7]
  PIN w_mask_in[8]
    DIRECTION INPUT ;
    USE SIGNAL ;
    SHAPE ABUTMENT ;
    PORT
      LAYER M4_m ;
      RECT 0.000 12.423 0.024 12.447 ;
    END
  END w_mask_in[8]
  PIN w_mask_in[9]
    DIRECTION INPUT ;
    USE SIGNAL ;
    SHAPE ABUTMENT ;
    PORT
      LAYER M4_m ;
      RECT 0.000 12.471 0.024 12.495 ;
    END
  END w_mask_in[9]
  PIN w_mask_in[10]
    DIRECTION INPUT ;
    USE SIGNAL ;
    SHAPE ABUTMENT ;
    PORT
      LAYER M4_m ;
      RECT 0.000 12.519 0.024 12.543 ;
    END
  END w_mask_in[10]
  PIN w_mask_in[11]
    DIRECTION INPUT ;
    USE SIGNAL ;
    SHAPE ABUTMENT ;
    PORT
      LAYER M4_m ;
      RECT 0.000 12.567 0.024 12.591 ;
    END
  END w_mask_in[11]
  PIN w_mask_in[12]
    DIRECTION INPUT ;
    USE SIGNAL ;
    SHAPE ABUTMENT ;
    PORT
      LAYER M4_m ;
      RECT 0.000 12.615 0.024 12.639 ;
    END
  END w_mask_in[12]
  PIN w_mask_in[13]
    DIRECTION INPUT ;
    USE SIGNAL ;
    SHAPE ABUTMENT ;
    PORT
      LAYER M4_m ;
      RECT 0.000 12.663 0.024 12.687 ;
    END
  END w_mask_in[13]
  PIN w_mask_in[14]
    DIRECTION INPUT ;
    USE SIGNAL ;
    SHAPE ABUTMENT ;
    PORT
      LAYER M4_m ;
      RECT 0.000 12.711 0.024 12.735 ;
    END
  END w_mask_in[14]
  PIN w_mask_in[15]
    DIRECTION INPUT ;
    USE SIGNAL ;
    SHAPE ABUTMENT ;
    PORT
      LAYER M4_m ;
      RECT 0.000 12.759 0.024 12.783 ;
    END
  END w_mask_in[15]
  PIN w_mask_in[16]
    DIRECTION INPUT ;
    USE SIGNAL ;
    SHAPE ABUTMENT ;
    PORT
      LAYER M4_m ;
      RECT 0.000 12.807 0.024 12.831 ;
    END
  END w_mask_in[16]
  PIN w_mask_in[17]
    DIRECTION INPUT ;
    USE SIGNAL ;
    SHAPE ABUTMENT ;
    PORT
      LAYER M4_m ;
      RECT 0.000 12.855 0.024 12.879 ;
    END
  END w_mask_in[17]
  PIN w_mask_in[18]
    DIRECTION INPUT ;
    USE SIGNAL ;
    SHAPE ABUTMENT ;
    PORT
      LAYER M4_m ;
      RECT 0.000 12.903 0.024 12.927 ;
    END
  END w_mask_in[18]
  PIN w_mask_in[19]
    DIRECTION INPUT ;
    USE SIGNAL ;
    SHAPE ABUTMENT ;
    PORT
      LAYER M4_m ;
      RECT 0.000 12.951 0.024 12.975 ;
    END
  END w_mask_in[19]
  PIN w_mask_in[20]
    DIRECTION INPUT ;
    USE SIGNAL ;
    SHAPE ABUTMENT ;
    PORT
      LAYER M4_m ;
      RECT 0.000 12.999 0.024 13.023 ;
    END
  END w_mask_in[20]
  PIN w_mask_in[21]
    DIRECTION INPUT ;
    USE SIGNAL ;
    SHAPE ABUTMENT ;
    PORT
      LAYER M4_m ;
      RECT 0.000 13.047 0.024 13.071 ;
    END
  END w_mask_in[21]
  PIN w_mask_in[22]
    DIRECTION INPUT ;
    USE SIGNAL ;
    SHAPE ABUTMENT ;
    PORT
      LAYER M4_m ;
      RECT 0.000 13.095 0.024 13.119 ;
    END
  END w_mask_in[22]
  PIN w_mask_in[23]
    DIRECTION INPUT ;
    USE SIGNAL ;
    SHAPE ABUTMENT ;
    PORT
      LAYER M4_m ;
      RECT 0.000 13.143 0.024 13.167 ;
    END
  END w_mask_in[23]
  PIN w_mask_in[24]
    DIRECTION INPUT ;
    USE SIGNAL ;
    SHAPE ABUTMENT ;
    PORT
      LAYER M4_m ;
      RECT 0.000 13.191 0.024 13.215 ;
    END
  END w_mask_in[24]
  PIN w_mask_in[25]
    DIRECTION INPUT ;
    USE SIGNAL ;
    SHAPE ABUTMENT ;
    PORT
      LAYER M4_m ;
      RECT 0.000 13.239 0.024 13.263 ;
    END
  END w_mask_in[25]
  PIN w_mask_in[26]
    DIRECTION INPUT ;
    USE SIGNAL ;
    SHAPE ABUTMENT ;
    PORT
      LAYER M4_m ;
      RECT 0.000 13.287 0.024 13.311 ;
    END
  END w_mask_in[26]
  PIN w_mask_in[27]
    DIRECTION INPUT ;
    USE SIGNAL ;
    SHAPE ABUTMENT ;
    PORT
      LAYER M4_m ;
      RECT 0.000 13.335 0.024 13.359 ;
    END
  END w_mask_in[27]
  PIN w_mask_in[28]
    DIRECTION INPUT ;
    USE SIGNAL ;
    SHAPE ABUTMENT ;
    PORT
      LAYER M4_m ;
      RECT 0.000 13.383 0.024 13.407 ;
    END
  END w_mask_in[28]
  PIN w_mask_in[29]
    DIRECTION INPUT ;
    USE SIGNAL ;
    SHAPE ABUTMENT ;
    PORT
      LAYER M4_m ;
      RECT 0.000 13.431 0.024 13.455 ;
    END
  END w_mask_in[29]
  PIN w_mask_in[30]
    DIRECTION INPUT ;
    USE SIGNAL ;
    SHAPE ABUTMENT ;
    PORT
      LAYER M4_m ;
      RECT 0.000 13.479 0.024 13.503 ;
    END
  END w_mask_in[30]
  PIN w_mask_in[31]
    DIRECTION INPUT ;
    USE SIGNAL ;
    SHAPE ABUTMENT ;
    PORT
      LAYER M4_m ;
      RECT 0.000 13.527 0.024 13.551 ;
    END
  END w_mask_in[31]
  PIN w_mask_in[32]
    DIRECTION INPUT ;
    USE SIGNAL ;
    SHAPE ABUTMENT ;
    PORT
      LAYER M4_m ;
      RECT 0.000 13.575 0.024 13.599 ;
    END
  END w_mask_in[32]
  PIN w_mask_in[33]
    DIRECTION INPUT ;
    USE SIGNAL ;
    SHAPE ABUTMENT ;
    PORT
      LAYER M4_m ;
      RECT 0.000 13.623 0.024 13.647 ;
    END
  END w_mask_in[33]
  PIN w_mask_in[34]
    DIRECTION INPUT ;
    USE SIGNAL ;
    SHAPE ABUTMENT ;
    PORT
      LAYER M4_m ;
      RECT 0.000 13.671 0.024 13.695 ;
    END
  END w_mask_in[34]
  PIN w_mask_in[35]
    DIRECTION INPUT ;
    USE SIGNAL ;
    SHAPE ABUTMENT ;
    PORT
      LAYER M4_m ;
      RECT 0.000 13.719 0.024 13.743 ;
    END
  END w_mask_in[35]
  PIN w_mask_in[36]
    DIRECTION INPUT ;
    USE SIGNAL ;
    SHAPE ABUTMENT ;
    PORT
      LAYER M4_m ;
      RECT 0.000 13.767 0.024 13.791 ;
    END
  END w_mask_in[36]
  PIN w_mask_in[37]
    DIRECTION INPUT ;
    USE SIGNAL ;
    SHAPE ABUTMENT ;
    PORT
      LAYER M4_m ;
      RECT 0.000 13.815 0.024 13.839 ;
    END
  END w_mask_in[37]
  PIN w_mask_in[38]
    DIRECTION INPUT ;
    USE SIGNAL ;
    SHAPE ABUTMENT ;
    PORT
      LAYER M4_m ;
      RECT 0.000 13.863 0.024 13.887 ;
    END
  END w_mask_in[38]
  PIN w_mask_in[39]
    DIRECTION INPUT ;
    USE SIGNAL ;
    SHAPE ABUTMENT ;
    PORT
      LAYER M4_m ;
      RECT 0.000 13.911 0.024 13.935 ;
    END
  END w_mask_in[39]
  PIN w_mask_in[40]
    DIRECTION INPUT ;
    USE SIGNAL ;
    SHAPE ABUTMENT ;
    PORT
      LAYER M4_m ;
      RECT 0.000 13.959 0.024 13.983 ;
    END
  END w_mask_in[40]
  PIN w_mask_in[41]
    DIRECTION INPUT ;
    USE SIGNAL ;
    SHAPE ABUTMENT ;
    PORT
      LAYER M4_m ;
      RECT 0.000 14.007 0.024 14.031 ;
    END
  END w_mask_in[41]
  PIN w_mask_in[42]
    DIRECTION INPUT ;
    USE SIGNAL ;
    SHAPE ABUTMENT ;
    PORT
      LAYER M4_m ;
      RECT 0.000 14.055 0.024 14.079 ;
    END
  END w_mask_in[42]
  PIN w_mask_in[43]
    DIRECTION INPUT ;
    USE SIGNAL ;
    SHAPE ABUTMENT ;
    PORT
      LAYER M4_m ;
      RECT 0.000 14.103 0.024 14.127 ;
    END
  END w_mask_in[43]
  PIN w_mask_in[44]
    DIRECTION INPUT ;
    USE SIGNAL ;
    SHAPE ABUTMENT ;
    PORT
      LAYER M4_m ;
      RECT 0.000 14.151 0.024 14.175 ;
    END
  END w_mask_in[44]
  PIN w_mask_in[45]
    DIRECTION INPUT ;
    USE SIGNAL ;
    SHAPE ABUTMENT ;
    PORT
      LAYER M4_m ;
      RECT 0.000 14.199 0.024 14.223 ;
    END
  END w_mask_in[45]
  PIN w_mask_in[46]
    DIRECTION INPUT ;
    USE SIGNAL ;
    SHAPE ABUTMENT ;
    PORT
      LAYER M4_m ;
      RECT 0.000 14.247 0.024 14.271 ;
    END
  END w_mask_in[46]
  PIN w_mask_in[47]
    DIRECTION INPUT ;
    USE SIGNAL ;
    SHAPE ABUTMENT ;
    PORT
      LAYER M4_m ;
      RECT 0.000 14.295 0.024 14.319 ;
    END
  END w_mask_in[47]
  PIN w_mask_in[48]
    DIRECTION INPUT ;
    USE SIGNAL ;
    SHAPE ABUTMENT ;
    PORT
      LAYER M4_m ;
      RECT 0.000 14.343 0.024 14.367 ;
    END
  END w_mask_in[48]
  PIN w_mask_in[49]
    DIRECTION INPUT ;
    USE SIGNAL ;
    SHAPE ABUTMENT ;
    PORT
      LAYER M4_m ;
      RECT 0.000 14.391 0.024 14.415 ;
    END
  END w_mask_in[49]
  PIN w_mask_in[50]
    DIRECTION INPUT ;
    USE SIGNAL ;
    SHAPE ABUTMENT ;
    PORT
      LAYER M4_m ;
      RECT 0.000 14.439 0.024 14.463 ;
    END
  END w_mask_in[50]
  PIN w_mask_in[51]
    DIRECTION INPUT ;
    USE SIGNAL ;
    SHAPE ABUTMENT ;
    PORT
      LAYER M4_m ;
      RECT 0.000 14.487 0.024 14.511 ;
    END
  END w_mask_in[51]
  PIN w_mask_in[52]
    DIRECTION INPUT ;
    USE SIGNAL ;
    SHAPE ABUTMENT ;
    PORT
      LAYER M4_m ;
      RECT 0.000 14.535 0.024 14.559 ;
    END
  END w_mask_in[52]
  PIN w_mask_in[53]
    DIRECTION INPUT ;
    USE SIGNAL ;
    SHAPE ABUTMENT ;
    PORT
      LAYER M4_m ;
      RECT 0.000 14.583 0.024 14.607 ;
    END
  END w_mask_in[53]
  PIN w_mask_in[54]
    DIRECTION INPUT ;
    USE SIGNAL ;
    SHAPE ABUTMENT ;
    PORT
      LAYER M4_m ;
      RECT 0.000 14.631 0.024 14.655 ;
    END
  END w_mask_in[54]
  PIN w_mask_in[55]
    DIRECTION INPUT ;
    USE SIGNAL ;
    SHAPE ABUTMENT ;
    PORT
      LAYER M4_m ;
      RECT 0.000 14.679 0.024 14.703 ;
    END
  END w_mask_in[55]
  PIN w_mask_in[56]
    DIRECTION INPUT ;
    USE SIGNAL ;
    SHAPE ABUTMENT ;
    PORT
      LAYER M4_m ;
      RECT 0.000 14.727 0.024 14.751 ;
    END
  END w_mask_in[56]
  PIN w_mask_in[57]
    DIRECTION INPUT ;
    USE SIGNAL ;
    SHAPE ABUTMENT ;
    PORT
      LAYER M4_m ;
      RECT 0.000 14.775 0.024 14.799 ;
    END
  END w_mask_in[57]
  PIN w_mask_in[58]
    DIRECTION INPUT ;
    USE SIGNAL ;
    SHAPE ABUTMENT ;
    PORT
      LAYER M4_m ;
      RECT 0.000 14.823 0.024 14.847 ;
    END
  END w_mask_in[58]
  PIN w_mask_in[59]
    DIRECTION INPUT ;
    USE SIGNAL ;
    SHAPE ABUTMENT ;
    PORT
      LAYER M4_m ;
      RECT 0.000 14.871 0.024 14.895 ;
    END
  END w_mask_in[59]
  PIN w_mask_in[60]
    DIRECTION INPUT ;
    USE SIGNAL ;
    SHAPE ABUTMENT ;
    PORT
      LAYER M4_m ;
      RECT 0.000 14.919 0.024 14.943 ;
    END
  END w_mask_in[60]
  PIN w_mask_in[61]
    DIRECTION INPUT ;
    USE SIGNAL ;
    SHAPE ABUTMENT ;
    PORT
      LAYER M4_m ;
      RECT 0.000 14.967 0.024 14.991 ;
    END
  END w_mask_in[61]
  PIN w_mask_in[62]
    DIRECTION INPUT ;
    USE SIGNAL ;
    SHAPE ABUTMENT ;
    PORT
      LAYER M4_m ;
      RECT 0.000 15.015 0.024 15.039 ;
    END
  END w_mask_in[62]
  PIN w_mask_in[63]
    DIRECTION INPUT ;
    USE SIGNAL ;
    SHAPE ABUTMENT ;
    PORT
      LAYER M4_m ;
      RECT 0.000 15.063 0.024 15.087 ;
    END
  END w_mask_in[63]
  PIN w_mask_in[64]
    DIRECTION INPUT ;
    USE SIGNAL ;
    SHAPE ABUTMENT ;
    PORT
      LAYER M4_m ;
      RECT 0.000 15.111 0.024 15.135 ;
    END
  END w_mask_in[64]
  PIN w_mask_in[65]
    DIRECTION INPUT ;
    USE SIGNAL ;
    SHAPE ABUTMENT ;
    PORT
      LAYER M4_m ;
      RECT 0.000 15.159 0.024 15.183 ;
    END
  END w_mask_in[65]
  PIN w_mask_in[66]
    DIRECTION INPUT ;
    USE SIGNAL ;
    SHAPE ABUTMENT ;
    PORT
      LAYER M4_m ;
      RECT 0.000 15.207 0.024 15.231 ;
    END
  END w_mask_in[66]
  PIN w_mask_in[67]
    DIRECTION INPUT ;
    USE SIGNAL ;
    SHAPE ABUTMENT ;
    PORT
      LAYER M4_m ;
      RECT 0.000 15.255 0.024 15.279 ;
    END
  END w_mask_in[67]
  PIN w_mask_in[68]
    DIRECTION INPUT ;
    USE SIGNAL ;
    SHAPE ABUTMENT ;
    PORT
      LAYER M4_m ;
      RECT 0.000 15.303 0.024 15.327 ;
    END
  END w_mask_in[68]
  PIN w_mask_in[69]
    DIRECTION INPUT ;
    USE SIGNAL ;
    SHAPE ABUTMENT ;
    PORT
      LAYER M4_m ;
      RECT 0.000 15.351 0.024 15.375 ;
    END
  END w_mask_in[69]
  PIN w_mask_in[70]
    DIRECTION INPUT ;
    USE SIGNAL ;
    SHAPE ABUTMENT ;
    PORT
      LAYER M4_m ;
      RECT 0.000 15.399 0.024 15.423 ;
    END
  END w_mask_in[70]
  PIN w_mask_in[71]
    DIRECTION INPUT ;
    USE SIGNAL ;
    SHAPE ABUTMENT ;
    PORT
      LAYER M4_m ;
      RECT 0.000 15.447 0.024 15.471 ;
    END
  END w_mask_in[71]
  PIN w_mask_in[72]
    DIRECTION INPUT ;
    USE SIGNAL ;
    SHAPE ABUTMENT ;
    PORT
      LAYER M4_m ;
      RECT 0.000 15.495 0.024 15.519 ;
    END
  END w_mask_in[72]
  PIN w_mask_in[73]
    DIRECTION INPUT ;
    USE SIGNAL ;
    SHAPE ABUTMENT ;
    PORT
      LAYER M4_m ;
      RECT 0.000 15.543 0.024 15.567 ;
    END
  END w_mask_in[73]
  PIN w_mask_in[74]
    DIRECTION INPUT ;
    USE SIGNAL ;
    SHAPE ABUTMENT ;
    PORT
      LAYER M4_m ;
      RECT 0.000 15.591 0.024 15.615 ;
    END
  END w_mask_in[74]
  PIN w_mask_in[75]
    DIRECTION INPUT ;
    USE SIGNAL ;
    SHAPE ABUTMENT ;
    PORT
      LAYER M4_m ;
      RECT 0.000 15.639 0.024 15.663 ;
    END
  END w_mask_in[75]
  PIN w_mask_in[76]
    DIRECTION INPUT ;
    USE SIGNAL ;
    SHAPE ABUTMENT ;
    PORT
      LAYER M4_m ;
      RECT 0.000 15.687 0.024 15.711 ;
    END
  END w_mask_in[76]
  PIN w_mask_in[77]
    DIRECTION INPUT ;
    USE SIGNAL ;
    SHAPE ABUTMENT ;
    PORT
      LAYER M4_m ;
      RECT 0.000 15.735 0.024 15.759 ;
    END
  END w_mask_in[77]
  PIN w_mask_in[78]
    DIRECTION INPUT ;
    USE SIGNAL ;
    SHAPE ABUTMENT ;
    PORT
      LAYER M4_m ;
      RECT 0.000 15.783 0.024 15.807 ;
    END
  END w_mask_in[78]
  PIN w_mask_in[79]
    DIRECTION INPUT ;
    USE SIGNAL ;
    SHAPE ABUTMENT ;
    PORT
      LAYER M4_m ;
      RECT 0.000 15.831 0.024 15.855 ;
    END
  END w_mask_in[79]
  PIN w_mask_in[80]
    DIRECTION INPUT ;
    USE SIGNAL ;
    SHAPE ABUTMENT ;
    PORT
      LAYER M4_m ;
      RECT 0.000 15.879 0.024 15.903 ;
    END
  END w_mask_in[80]
  PIN w_mask_in[81]
    DIRECTION INPUT ;
    USE SIGNAL ;
    SHAPE ABUTMENT ;
    PORT
      LAYER M4_m ;
      RECT 0.000 15.927 0.024 15.951 ;
    END
  END w_mask_in[81]
  PIN w_mask_in[82]
    DIRECTION INPUT ;
    USE SIGNAL ;
    SHAPE ABUTMENT ;
    PORT
      LAYER M4_m ;
      RECT 0.000 15.975 0.024 15.999 ;
    END
  END w_mask_in[82]
  PIN w_mask_in[83]
    DIRECTION INPUT ;
    USE SIGNAL ;
    SHAPE ABUTMENT ;
    PORT
      LAYER M4_m ;
      RECT 0.000 16.023 0.024 16.047 ;
    END
  END w_mask_in[83]
  PIN w_mask_in[84]
    DIRECTION INPUT ;
    USE SIGNAL ;
    SHAPE ABUTMENT ;
    PORT
      LAYER M4_m ;
      RECT 0.000 16.071 0.024 16.095 ;
    END
  END w_mask_in[84]
  PIN w_mask_in[85]
    DIRECTION INPUT ;
    USE SIGNAL ;
    SHAPE ABUTMENT ;
    PORT
      LAYER M4_m ;
      RECT 0.000 16.119 0.024 16.143 ;
    END
  END w_mask_in[85]
  PIN w_mask_in[86]
    DIRECTION INPUT ;
    USE SIGNAL ;
    SHAPE ABUTMENT ;
    PORT
      LAYER M4_m ;
      RECT 0.000 16.167 0.024 16.191 ;
    END
  END w_mask_in[86]
  PIN w_mask_in[87]
    DIRECTION INPUT ;
    USE SIGNAL ;
    SHAPE ABUTMENT ;
    PORT
      LAYER M4_m ;
      RECT 0.000 16.215 0.024 16.239 ;
    END
  END w_mask_in[87]
  PIN w_mask_in[88]
    DIRECTION INPUT ;
    USE SIGNAL ;
    SHAPE ABUTMENT ;
    PORT
      LAYER M4_m ;
      RECT 0.000 16.263 0.024 16.287 ;
    END
  END w_mask_in[88]
  PIN w_mask_in[89]
    DIRECTION INPUT ;
    USE SIGNAL ;
    SHAPE ABUTMENT ;
    PORT
      LAYER M4_m ;
      RECT 0.000 16.311 0.024 16.335 ;
    END
  END w_mask_in[89]
  PIN w_mask_in[90]
    DIRECTION INPUT ;
    USE SIGNAL ;
    SHAPE ABUTMENT ;
    PORT
      LAYER M4_m ;
      RECT 0.000 16.359 0.024 16.383 ;
    END
  END w_mask_in[90]
  PIN w_mask_in[91]
    DIRECTION INPUT ;
    USE SIGNAL ;
    SHAPE ABUTMENT ;
    PORT
      LAYER M4_m ;
      RECT 0.000 16.407 0.024 16.431 ;
    END
  END w_mask_in[91]
  PIN w_mask_in[92]
    DIRECTION INPUT ;
    USE SIGNAL ;
    SHAPE ABUTMENT ;
    PORT
      LAYER M4_m ;
      RECT 0.000 16.455 0.024 16.479 ;
    END
  END w_mask_in[92]
  PIN w_mask_in[93]
    DIRECTION INPUT ;
    USE SIGNAL ;
    SHAPE ABUTMENT ;
    PORT
      LAYER M4_m ;
      RECT 0.000 16.503 0.024 16.527 ;
    END
  END w_mask_in[93]
  PIN w_mask_in[94]
    DIRECTION INPUT ;
    USE SIGNAL ;
    SHAPE ABUTMENT ;
    PORT
      LAYER M4_m ;
      RECT 0.000 16.551 0.024 16.575 ;
    END
  END w_mask_in[94]
  PIN w_mask_in[95]
    DIRECTION INPUT ;
    USE SIGNAL ;
    SHAPE ABUTMENT ;
    PORT
      LAYER M4_m ;
      RECT 0.000 16.599 0.024 16.623 ;
    END
  END w_mask_in[95]
  PIN w_mask_in[96]
    DIRECTION INPUT ;
    USE SIGNAL ;
    SHAPE ABUTMENT ;
    PORT
      LAYER M4_m ;
      RECT 0.000 16.647 0.024 16.671 ;
    END
  END w_mask_in[96]
  PIN w_mask_in[97]
    DIRECTION INPUT ;
    USE SIGNAL ;
    SHAPE ABUTMENT ;
    PORT
      LAYER M4_m ;
      RECT 0.000 16.695 0.024 16.719 ;
    END
  END w_mask_in[97]
  PIN w_mask_in[98]
    DIRECTION INPUT ;
    USE SIGNAL ;
    SHAPE ABUTMENT ;
    PORT
      LAYER M4_m ;
      RECT 0.000 16.743 0.024 16.767 ;
    END
  END w_mask_in[98]
  PIN w_mask_in[99]
    DIRECTION INPUT ;
    USE SIGNAL ;
    SHAPE ABUTMENT ;
    PORT
      LAYER M4_m ;
      RECT 0.000 16.791 0.024 16.815 ;
    END
  END w_mask_in[99]
  PIN w_mask_in[100]
    DIRECTION INPUT ;
    USE SIGNAL ;
    SHAPE ABUTMENT ;
    PORT
      LAYER M4_m ;
      RECT 0.000 16.839 0.024 16.863 ;
    END
  END w_mask_in[100]
  PIN w_mask_in[101]
    DIRECTION INPUT ;
    USE SIGNAL ;
    SHAPE ABUTMENT ;
    PORT
      LAYER M4_m ;
      RECT 0.000 16.887 0.024 16.911 ;
    END
  END w_mask_in[101]
  PIN w_mask_in[102]
    DIRECTION INPUT ;
    USE SIGNAL ;
    SHAPE ABUTMENT ;
    PORT
      LAYER M4_m ;
      RECT 0.000 16.935 0.024 16.959 ;
    END
  END w_mask_in[102]
  PIN w_mask_in[103]
    DIRECTION INPUT ;
    USE SIGNAL ;
    SHAPE ABUTMENT ;
    PORT
      LAYER M4_m ;
      RECT 0.000 16.983 0.024 17.007 ;
    END
  END w_mask_in[103]
  PIN w_mask_in[104]
    DIRECTION INPUT ;
    USE SIGNAL ;
    SHAPE ABUTMENT ;
    PORT
      LAYER M4_m ;
      RECT 0.000 17.031 0.024 17.055 ;
    END
  END w_mask_in[104]
  PIN w_mask_in[105]
    DIRECTION INPUT ;
    USE SIGNAL ;
    SHAPE ABUTMENT ;
    PORT
      LAYER M4_m ;
      RECT 0.000 17.079 0.024 17.103 ;
    END
  END w_mask_in[105]
  PIN w_mask_in[106]
    DIRECTION INPUT ;
    USE SIGNAL ;
    SHAPE ABUTMENT ;
    PORT
      LAYER M4_m ;
      RECT 0.000 17.127 0.024 17.151 ;
    END
  END w_mask_in[106]
  PIN w_mask_in[107]
    DIRECTION INPUT ;
    USE SIGNAL ;
    SHAPE ABUTMENT ;
    PORT
      LAYER M4_m ;
      RECT 0.000 17.175 0.024 17.199 ;
    END
  END w_mask_in[107]
  PIN w_mask_in[108]
    DIRECTION INPUT ;
    USE SIGNAL ;
    SHAPE ABUTMENT ;
    PORT
      LAYER M4_m ;
      RECT 0.000 17.223 0.024 17.247 ;
    END
  END w_mask_in[108]
  PIN w_mask_in[109]
    DIRECTION INPUT ;
    USE SIGNAL ;
    SHAPE ABUTMENT ;
    PORT
      LAYER M4_m ;
      RECT 0.000 17.271 0.024 17.295 ;
    END
  END w_mask_in[109]
  PIN w_mask_in[110]
    DIRECTION INPUT ;
    USE SIGNAL ;
    SHAPE ABUTMENT ;
    PORT
      LAYER M4_m ;
      RECT 0.000 17.319 0.024 17.343 ;
    END
  END w_mask_in[110]
  PIN w_mask_in[111]
    DIRECTION INPUT ;
    USE SIGNAL ;
    SHAPE ABUTMENT ;
    PORT
      LAYER M4_m ;
      RECT 0.000 17.367 0.024 17.391 ;
    END
  END w_mask_in[111]
  PIN w_mask_in[112]
    DIRECTION INPUT ;
    USE SIGNAL ;
    SHAPE ABUTMENT ;
    PORT
      LAYER M4_m ;
      RECT 0.000 17.415 0.024 17.439 ;
    END
  END w_mask_in[112]
  PIN w_mask_in[113]
    DIRECTION INPUT ;
    USE SIGNAL ;
    SHAPE ABUTMENT ;
    PORT
      LAYER M4_m ;
      RECT 0.000 17.463 0.024 17.487 ;
    END
  END w_mask_in[113]
  PIN w_mask_in[114]
    DIRECTION INPUT ;
    USE SIGNAL ;
    SHAPE ABUTMENT ;
    PORT
      LAYER M4_m ;
      RECT 0.000 17.511 0.024 17.535 ;
    END
  END w_mask_in[114]
  PIN w_mask_in[115]
    DIRECTION INPUT ;
    USE SIGNAL ;
    SHAPE ABUTMENT ;
    PORT
      LAYER M4_m ;
      RECT 0.000 17.559 0.024 17.583 ;
    END
  END w_mask_in[115]
  PIN w_mask_in[116]
    DIRECTION INPUT ;
    USE SIGNAL ;
    SHAPE ABUTMENT ;
    PORT
      LAYER M4_m ;
      RECT 0.000 17.607 0.024 17.631 ;
    END
  END w_mask_in[116]
  PIN w_mask_in[117]
    DIRECTION INPUT ;
    USE SIGNAL ;
    SHAPE ABUTMENT ;
    PORT
      LAYER M4_m ;
      RECT 0.000 17.655 0.024 17.679 ;
    END
  END w_mask_in[117]
  PIN w_mask_in[118]
    DIRECTION INPUT ;
    USE SIGNAL ;
    SHAPE ABUTMENT ;
    PORT
      LAYER M4_m ;
      RECT 0.000 17.703 0.024 17.727 ;
    END
  END w_mask_in[118]
  PIN w_mask_in[119]
    DIRECTION INPUT ;
    USE SIGNAL ;
    SHAPE ABUTMENT ;
    PORT
      LAYER M4_m ;
      RECT 0.000 17.751 0.024 17.775 ;
    END
  END w_mask_in[119]
  PIN w_mask_in[120]
    DIRECTION INPUT ;
    USE SIGNAL ;
    SHAPE ABUTMENT ;
    PORT
      LAYER M4_m ;
      RECT 0.000 17.799 0.024 17.823 ;
    END
  END w_mask_in[120]
  PIN w_mask_in[121]
    DIRECTION INPUT ;
    USE SIGNAL ;
    SHAPE ABUTMENT ;
    PORT
      LAYER M4_m ;
      RECT 0.000 17.847 0.024 17.871 ;
    END
  END w_mask_in[121]
  PIN w_mask_in[122]
    DIRECTION INPUT ;
    USE SIGNAL ;
    SHAPE ABUTMENT ;
    PORT
      LAYER M4_m ;
      RECT 0.000 17.895 0.024 17.919 ;
    END
  END w_mask_in[122]
  PIN w_mask_in[123]
    DIRECTION INPUT ;
    USE SIGNAL ;
    SHAPE ABUTMENT ;
    PORT
      LAYER M4_m ;
      RECT 0.000 17.943 0.024 17.967 ;
    END
  END w_mask_in[123]
  PIN addr_in[0]
    DIRECTION INPUT ;
    USE SIGNAL ;
    SHAPE ABUTMENT ;
    PORT
      LAYER M4_m ;
      RECT 0.000 18.039 0.024 18.063 ;
    END
  END addr_in[0]
  PIN addr_in[1]
    DIRECTION INPUT ;
    USE SIGNAL ;
    SHAPE ABUTMENT ;
    PORT
      LAYER M4_m ;
      RECT 0.000 18.087 0.024 18.111 ;
    END
  END addr_in[1]
  PIN addr_in[2]
    DIRECTION INPUT ;
    USE SIGNAL ;
    SHAPE ABUTMENT ;
    PORT
      LAYER M4_m ;
      RECT 0.000 18.135 0.024 18.159 ;
    END
  END addr_in[2]
  PIN addr_in[3]
    DIRECTION INPUT ;
    USE SIGNAL ;
    SHAPE ABUTMENT ;
    PORT
      LAYER M4_m ;
      RECT 0.000 18.183 0.024 18.207 ;
    END
  END addr_in[3]
  PIN addr_in[4]
    DIRECTION INPUT ;
    USE SIGNAL ;
    SHAPE ABUTMENT ;
    PORT
      LAYER M4_m ;
      RECT 0.000 18.231 0.024 18.255 ;
    END
  END addr_in[4]
  PIN addr_in[5]
    DIRECTION INPUT ;
    USE SIGNAL ;
    SHAPE ABUTMENT ;
    PORT
      LAYER M4_m ;
      RECT 0.000 18.279 0.024 18.303 ;
    END
  END addr_in[5]
  PIN we_in
    DIRECTION INPUT ;
    USE SIGNAL ;
    SHAPE ABUTMENT ;
    PORT
      LAYER M4_m ;
      RECT 0.000 18.375 0.024 18.399 ;
    END
  END we_in
  PIN ce_in
    DIRECTION INPUT ;
    USE SIGNAL ;
    SHAPE ABUTMENT ;
    PORT
      LAYER M4_m ;
      RECT 0.000 18.423 0.024 18.447 ;
    END
  END ce_in
  PIN clk
    DIRECTION INPUT ;
    USE SIGNAL ;
    SHAPE ABUTMENT ;
    PORT
      LAYER M4_m ;
      RECT 0.000 18.471 0.024 18.495 ;
    END
  END clk
  PIN VSS
    DIRECTION INOUT ;
    USE GROUND ;
    PORT
      LAYER M4_m ;
      RECT 0.048 0.000 16.102 0.096 ;
      RECT 0.048 0.768 16.102 0.864 ;
      RECT 0.048 1.536 16.102 1.632 ;
      RECT 0.048 2.304 16.102 2.400 ;
      RECT 0.048 3.072 16.102 3.168 ;
      RECT 0.048 3.840 16.102 3.936 ;
      RECT 0.048 4.608 16.102 4.704 ;
      RECT 0.048 5.376 16.102 5.472 ;
      RECT 0.048 6.144 16.102 6.240 ;
      RECT 0.048 6.912 16.102 7.008 ;
      RECT 0.048 7.680 16.102 7.776 ;
      RECT 0.048 8.448 16.102 8.544 ;
      RECT 0.048 9.216 16.102 9.312 ;
      RECT 0.048 9.984 16.102 10.080 ;
      RECT 0.048 10.752 16.102 10.848 ;
      RECT 0.048 11.520 16.102 11.616 ;
      RECT 0.048 12.288 16.102 12.384 ;
      RECT 0.048 13.056 16.102 13.152 ;
      RECT 0.048 13.824 16.102 13.920 ;
      RECT 0.048 14.592 16.102 14.688 ;
      RECT 0.048 15.360 16.102 15.456 ;
      RECT 0.048 16.128 16.102 16.224 ;
      RECT 0.048 16.896 16.102 16.992 ;
      RECT 0.048 17.664 16.102 17.760 ;
      RECT 0.048 18.432 16.102 18.528 ;
      RECT 0.048 19.200 16.102 19.296 ;
      RECT 0.048 19.968 16.102 20.064 ;
      RECT 0.048 20.736 16.102 20.832 ;
    END
  END VSS
  PIN VDD
    DIRECTION INOUT ;
    USE POWER ;
    PORT
      LAYER M4_m ;
      RECT 0.048 0.384 16.102 0.480 ;
      RECT 0.048 1.152 16.102 1.248 ;
      RECT 0.048 1.920 16.102 2.016 ;
      RECT 0.048 2.688 16.102 2.784 ;
      RECT 0.048 3.456 16.102 3.552 ;
      RECT 0.048 4.224 16.102 4.320 ;
      RECT 0.048 4.992 16.102 5.088 ;
      RECT 0.048 5.760 16.102 5.856 ;
      RECT 0.048 6.528 16.102 6.624 ;
      RECT 0.048 7.296 16.102 7.392 ;
      RECT 0.048 8.064 16.102 8.160 ;
      RECT 0.048 8.832 16.102 8.928 ;
      RECT 0.048 9.600 16.102 9.696 ;
      RECT 0.048 10.368 16.102 10.464 ;
      RECT 0.048 11.136 16.102 11.232 ;
      RECT 0.048 11.904 16.102 12.000 ;
      RECT 0.048 12.672 16.102 12.768 ;
      RECT 0.048 13.440 16.102 13.536 ;
      RECT 0.048 14.208 16.102 14.304 ;
      RECT 0.048 14.976 16.102 15.072 ;
      RECT 0.048 15.744 16.102 15.840 ;
      RECT 0.048 16.512 16.102 16.608 ;
      RECT 0.048 17.280 16.102 17.376 ;
      RECT 0.048 18.048 16.102 18.144 ;
      RECT 0.048 18.816 16.102 18.912 ;
      RECT 0.048 19.584 16.102 19.680 ;
      RECT 0.048 20.352 16.102 20.448 ;
    END
  END VDD
  OBS
    LAYER M1_m ;
    RECT 0 0 16.150 21.000 ;
    LAYER M2_m ;
    RECT 0 0 16.150 21.000 ;
    LAYER M3_m ;
    RECT 0.059 0.000 16.150 21.000 ;
    LAYER M4_m ;
    RECT 0.059 18.543 16.150 21.000 ;
  END
END fakeram7_64x124_upper

END LIBRARY
